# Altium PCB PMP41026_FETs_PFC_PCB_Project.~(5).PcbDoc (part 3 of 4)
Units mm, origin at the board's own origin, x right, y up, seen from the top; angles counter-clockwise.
Board outline 62 x 36 mm, 6 copper layers (Top Layer, Signal Layer 1, Signal Layer 2, Signal Layer 3, Signal Layer 4, Bottom Layer), stack 1.773 mm thick; 61 components, 66 nets, 254 pads, 775 vias.
Unrouted connection lines stored in the file: 2.

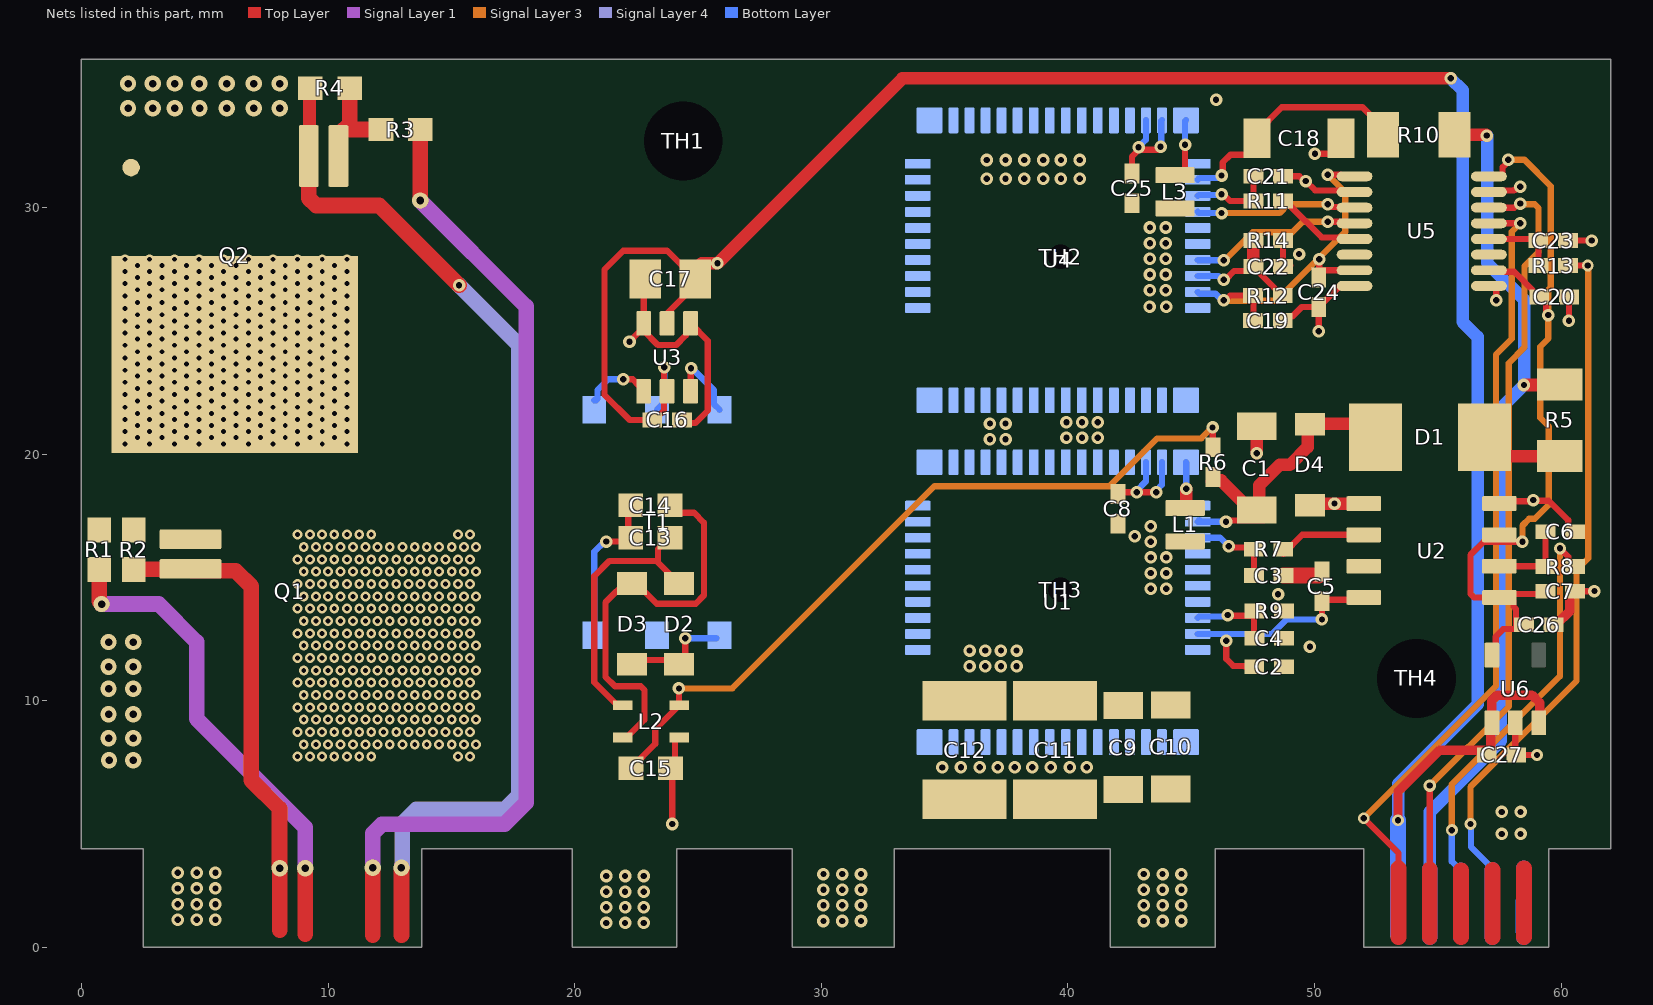
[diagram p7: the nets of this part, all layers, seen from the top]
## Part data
C1 C18: library part CMP-0008692-2, "CAP, CERM, 10 uF, 25 V, +/- 20%, X7R, 1206_190", Cap_Case=1206, Manufacturer=TDK, Supplier Part Number 1=445-6812-1-ND, TempCo=X7R, Tolerance_%=20%, Value1=Unknown, Value2=25V, ValueDisplayed=10uF
C2 C19: library part CMP-0860563-1, "CAP, CERM, 0.22 µF, 16 V,+/- 10%, X7R, 0402", Cap_Case=0402, Manufacturer="Samsung Electro-Mechanics", TempCo=X7R, Tolerance_%=10%, Value2=16V, ValueDisplayed=0.22µF
C3 C4 C6 C21 C22 C23: library part CMP-0006196-2, "CAP, CERM, 100 pF, 50 V, +/- 1%, C0G/NP0, 0402", Cap_Case=0402, Manufacturer=AVX, Supplier Part Number 1=478-3658-1-ND, TempCo=C0G/NP0, Tolerance_%=1%, Value1=Unknown, Value2=50V, ValueDisplayed=100pF
C5 C16 C24: library part CMP-0006297-2, "CAP, CERM, 0.1 uF, 50 V, +/- 10%, X7R, 0402", Alternate Manufacturer="Wurth Elektronik", Alternate PartNumber=885012205037, Cap_Case=0402, Manufacturer=TDK, Supplier Part Number 1=445-5932-1-ND, TempCo=X7R, Tolerance_%=10%, Value1="0.039064 ohm", Value2=50V, ValueDisplayed=0.1uF
C7 C20: library part CMP-0006276-2, "CAP, CERM, 1 uF, 25 V, +/- 10%, X5R, 0402", Alternate Manufacturer=TDK, Alternate PartNumber=C1005X5R1E225K050BC, Cap_Case=0402, Supplier Part Number 1=445-9066-1-ND, TempCo=X5R, Tolerance_%=10%, Value1=Unknown, Value2=25V, ValueDisplayed=1uF
C8 C25: library part CMP-0006716-2, "CAP, CERM, 2.2 uF, 25 V, +/- 10%, X5R, AEC-Q200 Grade 3, 0402", Cap_Case=0402, Manufacturer=MuRata, Supplier Part Number 1=490-12267-1-ND, TempCo=X5R, Tolerance_%=10%, Value1=Unknown, Value2=25V, ValueDisplayed=2.2uF
C9 C10: library part CMP-0084048-1, "CAP, CERM, 0.022 µF, 1000 V,+/- 10%, X7R, AEC-Q200 Grade 1, 1206", Cap_Case=1206, Manufacturer=Kemet, TempCo=X7R, Tolerance_%=10%, Value2=1000V, ValueDisplayed=0.022µF
C11 C12: library part CMP-0009326-2, "CAP, CERM, 0.1 uF, 1000 V, +/- 10%, X7R, 1812", Cap_Case=1812, Manufacturer=Kemet, Supplier Part Number 1=399-6523-1-ND, TempCo=X7R, Tolerance_%=10%, Value1=Unknown, Value2=1000V, ValueDisplayed=0.1uF
C13 C14 C15: library part CMP-0007022-5, "CAP, CERM, 4.7 uF, 35 V, +/- 10%, X5R, 0603", Cap_Case=0603, Manufacturer=TDK, Supplier Part Number 1=445-9064-1-ND, TempCo=X5R, Tolerance_%=10%, Value1="0.003728 ohm", Value2=35V, ValueDisplayed=4.7uF
C17: library part CMP-0008020-2, "CAP, CERM, 4.7 uF, 16 V, +/- 10%, X7R, AEC-Q200 Grade 1, 0805", Cap_Case=0805, Manufacturer=MuRata, Supplier Part Number 1=490-5332-1-ND, TempCo=X7R, Tolerance_%=10%, Value1=Unknown, Value2=16V, ValueDisplayed=4.7uF
C26 C27: library part CMP-0006623-2, "CAP, CERM, 0.1 uF, 6.3 V, +/- 10%, X7R, 0402", Cap_Case=0402, Manufacturer=MuRata, Supplier Part Number 1=GRM155R70J104KA01D-ND, TempCo=X7R, Tolerance_%=10%, Value1=Unknown, Value2=6.3V, ValueDisplayed=0.1uF
D1: library part CMP-0076998-2, "Diode, Schottky, 650 V, 1 A, SMB", Manufacturer="GeneSiC Semiconductor", Value1=1A, Value2=2V
D2 D3: library part CMP-0028524-2, "Diode, Schottky, 20 V, 0.5 A, SOD-123", Manufacturer="ON Semiconductor", Value1=0.5A, Value2=0.385V
D4: library part CMP-0005769-4, "Diode, Zener, 16 V, 500 mW, AEC-Q101, SOD-123", Manufacturer="Diodes Inc.", Power_W=500mW, Value1=0.5W
L1 L3: library part CMP-0089347-1, "4.7µH Unshielded Inductor 1.1A 426mOhm Max 0806 (2016 Metric)", Digikey Part Number=2037-SDEM20161T-4R7MSCT-ND, Manufacturer=Cyntec, Operating Temperature Range="-55°C to +125°C", Test Frequency=1MHz, Tolerance_%=20%
L2: library part CMP-0013161-2, "Coupled inductor, 0.2 A, 0.45 ohm, SMD", Manufacturer=TDK, Supplier Part Number 1=445-8930-1-ND
Q1 Q2: library part CMP-0086487-1, "N-Channel 600V 23A (Tc) 390W (Tc) Surface Mount PG-HSOF-8-2", Manufacturer=Infineon
R1 R3: library part CMP-0022003-4, "RES, 10.0, 1%, 0.1 W, AEC-Q200 Grade 0, 0603", Manufacturer=Vishay-Dale, Power_W=100mW, Supplier Part Number 1=541-10.0HCT-ND, TempCo="100 ppm/C", Tolerance_%=1%, Value2=0.1W, Value_Code=10R0, ValueDisplayed=10.0
R2 R4: library part CMP-0021998-4, "RES, 10.0 k, 1%, 0.1 W, AEC-Q200 Grade 0, 0603", Manufacturer=Vishay-Dale, Power_W=100mW, Supplier Part Number 1=541-10.0KHCT-ND, TempCo="100 ppm/C", Tolerance_%=1%, Value2=0.1W, Value_Code=10k0, ValueDisplayed=10.0k
R5: library part CMP-0018623-3, "RES, 1.8, 5%, 0.25 W, AEC-Q200 Grade 0, 1206", Manufacturer=Vishay-Dale, Power_W=250mW, Supplier Part Number 1=541-1.8ECT-ND, TempCo="200 ppm/C", Tolerance_%=5%, Value2=0.25W, Value_Code=1R80, ValueDisplayed=1.8
R6 R12: library part CMP-0026992-3, "RES, 0, 5%, 0.1 W, AEC-Q200 Grade 0, 0402", Manufacturer=Panasonic, Power_W=100mW, Supplier Part Number 1=P0.0JCT-ND, TempCo="600 ppm/C", Tolerance_%=5%, Value2=0.1W, Value_Code=0000, ValueDisplayed=0
R7 R8 R11 R13: library part CMP-0026738-1, "RES, 49.9, 1%, 0.063 W, 0402", Manufacturer="Yageo America", Power_W=63mW, Supplier Part Number 1=311-49.9LRCT-ND, TempCo="100 ppm/C", Tolerance_%=1%, Value2=0.063W, Value_Code=49R9, ValueDisplayed=49.9
R9 R14: library part CMP-0026162-1, "RES, 20.0 k, 1%, 0.063 W, 0402", Manufacturer=Vishay-Dale, Power_W=63mW, Supplier Part Number 1=541-20.0KLCT-ND, TempCo="100 ppm/C", Tolerance_%=1%, Value2=0.063W, Value_Code=20k0, ValueDisplayed=20.0k
R10: library part CMP-0018748-3, "RES, 0, 5%, 0.25 W, AEC-Q200 Grade 0, 1206", Manufacturer=Panasonic, Power_W=250mW, Supplier Part Number 1=P0.0ECT-ND, TempCo="600 ppm/C", Tolerance_%=5%, Value2=0.25W, Value_Code=0000, ValueDisplayed=0
T1: library part CMP-0030718-1, "Transformer, 475uH, SMT", Manufacturer="Wurth Elektronik", Supplier Part Number 1=732-4458-1-ND, ValueDisplayed=475uH
TH1 TH2 TH3 TH4: library part CMP-0003719-1, "Testpoint", Manufacturer="Texas Instruments", PartNumber=TP_H0.45P0.75
U1 U4: library part CMP-0089968-1, "650-V 30-m? GaN FET with Integrated Driver and Protection", Manufacturer="Texas Instruments", Max Supply Voltage=18V, Min Supply Voltage=7.5V, Nominal Supply Current=540uA, Operating Temperature Range="-40°C to +125°C", Output Voltage=520V
U2: library part CMP-0082403-1, "Automotive, High Speed, Robust EMC Reinforced Single-Channel Digital Isolator, D0008B (SOIC-8)", Alternate Manufacturer="Texas Instruments", Alternate PartNumber=ISO7710FQDRQ1, Operating Temperature Range="-40 to 125 C", Rating=Automotive
U3: library part CMP-0076095-1, "Low-Noise 1 A, 420 kHz Transformer Driver, DBV0006A (SOT-23-6)", Alternate Manufacturer="Texas Instruments", Alternate PartNumber=SN6505BDBVT
U5: library part CMP-0078719-1, "High Speed, Robust EMC Triple-Channel Digital Isolators, DBQ0016A (SSOP-16)", Alternate Manufacturer="Texas Instruments", Alternate PartNumber=ISO7731FDBQ
U6: library part CMP-0065092-2, "Low-Dropout Regulator, DBV0005A (SOT-23-5)", Alternate Manufacturer="Texas Instruments"

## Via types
v1: diameter 0.403, hole 0.2, Top Layer to Bottom Layer, 568 vias
v2: diameter 0.508, hole 0.254, Top Layer to Bottom Layer, 151 vias
v3: diameter 0.66/0.66/0.66/0.66/0.66/0.66 (per signal layer), hole 0.305, Top Layer to Bottom Layer, 32 vias
v4: diameter 0.508, hole 0.254, Top Layer to Bottom Layer, tented top, 11 vias
v5: diameter 0.483, hole 0.254, Top Layer to Bottom Layer, tented both sides, 7 vias
v6: diameter 0.508, hole 0.254, Top Layer to Bottom Layer, tented both sides, 6 vias

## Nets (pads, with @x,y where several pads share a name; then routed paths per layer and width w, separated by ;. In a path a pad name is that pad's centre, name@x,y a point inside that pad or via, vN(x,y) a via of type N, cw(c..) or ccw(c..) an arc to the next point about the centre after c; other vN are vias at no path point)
3V3: C7.1 C20.2 C26.1 U2.1 U2.3 U5.10 U5.16 U6.5 | length 32.5
  Top Layer w0.254: U6.5@57.208,11.934 57.343,12.07 57.343,12.599 57.649,12.904 C26.1@58.164,12.904 ; U5.16@57.357,31.261 57.554,31.261 57.622,31.328 57.622,31.631 57.851,31.86 v2(57.851,31.929) ; U2.1@57.494,14.074 58.004,14.074 58.067,14.011 58.067,13.814 58.164,13.718 C26.1@58.164,12.904 ; U2.3@57.494,16.724 U2.3@57.919,16.724 ; U5.10@57.519,27.387 58.097,27.387 C20.2@59.113,26.371 ; v6(58.429,16.441) 56.852,16.441 56.321,15.91 56.321,14.333 56.47,14.184 U2.1@57.494,14.184 57.639,14.328 59.251,14.328 C7.1@59.36,14.438 ; C26.1@58.491,13.077 58.318,12.904 C26.1@58.164,12.904 ; C20.2@59.17,26.244 59.34,26.244 59.386,26.198 v4@59.386,25.794
  Signal Layer 3 w0.254: v2(57.851,31.929) 58.512,31.929 59.578,30.863 59.578,26.757 59.477,26.656 v4(59.477,25.634) 59.477,24.682 59.146,24.351 59.146,21.471 59.496,21.121 59.496,17.939 58.93,17.373 58.698,17.373 58.429,17.104 v6(58.429,16.441)
5V: C16.1 C17.1 C27.1 T1.5 U3.2 U3.5 U6.1 U6.3 | length 97.5
  Top Layer w0.254: C16.1@22.857,21.384 22.222,21.384 21.206,22.4 21.206,27.48 21.968,28.242 23.746,28.242 C17.1@24.889,27.099 ; C16.1@23.119,21.257 23.619,21.757 U3.2@23.619,22.4 ; U3.2@23.619,22.969 23.619,23.51 v2(23.63,23.521) ; U3.5@23.746,25.702 C17.1@24.889,26.845
  Top Layer w0.381: v5(53.381,5.15) 53.381,6.31 55.068,7.997 56.972,7.997 57.034,7.997 57.144,8.106 57.144,9.057 U6.1@57.188,9.101 57.188,10.003 57.412,10.226 58.813,10.226 59.127,9.912 59.127,9.14 U6.3@59.088,9.101
  Top Layer w0.508: C17.1@25.143,27.734 v4(25.786,27.734) 33.287,35.234 v2(55.519,35.234)
  Bottom Layer w0.254: T1.5@23.335,21.8 23.63,22.095 v2(23.63,23.521)
  Bottom Layer w0.508: v5@53.4,5.233 53.4,6.639 56.608,9.847 56.608,24.75 56,25.358 56,34.753 v2(55.519,35.234)
  Bottom Layer w0.635: 53.381,0.521 v5(53.381,5.15)
5V_H: C2.2 C5.1 U1.51 U2.8 | length 9.9
  Top Layer w0.254: v2(46.422,12.433) 46.422,11.694 46.705,11.411 C2.2@47.444,11.411 ; C2.2@47.197,11.369 47.486,11.369 C2.2@47.444,11.411 ; v4(50.299,13.295) C5.1@50.299,13.93 ; C5.1@50.299,14.092 U2.8@51.604,14.092 ; C2.2@47.444,11.411 47.197,11.411 C2.2@47.444,11.411
  Bottom Layer w0.254: U1.51@45.261,12.708 46.476,12.708 48.286,12.708 48.872,13.295 v4(50.299,13.295)
5V_L: C19.2 C24.2 R12.1 U4.51 U5.1 U5.7 | length 14.5
  Top Layer w0.254: v2(46.318,26.232) 46.387,26.232 46.582,26.427 R12.1@47.507,26.427 47.521,26.427 47.521,25.736 ; C24.2@50.171,27.162 50.191,27.182 C24.2@50.191,27.451 ; v2(50.191,27.895) C24.2@50.191,27.451 ; v2(50.534,31.324) U5.1@51.042,31.324 ; U5.7@51.619,27.451 C24.2@50.191,27.451
  Signal Layer 3 w0.254: v2@46.335,26.214 48.448,26.214 51.241,29.008 51.241,30.617 v2(50.534,31.324)
  Bottom Layer w0.254: U4.51@45.261,26.571 45.334,26.498 45.983,26.498 46.266,26.214 v2@46.335,26.214
12V: R5.1 R10.1 | length 38.6
  Top Layer w0.508: R10.1@55.681,32.946 56.95,32.946 v6(56.981,32.916) ; v2(58.491,22.801) 59.931,22.801 R5.1@59.948,22.817
  Bottom Layer w0.508: 54.666,2.092 54.67,2.097 54.67,5.488 57.551,8.369 57.551,21.861 58.51,22.82 58.51,26.241 57,27.751 57,32.897 v6(56.981,32.916)
  Bottom Layer w0.635: 54.666,0.415 54.673,3.168
+BRDG_N: R1.1 | length 19.6
  Top Layer w0.635: R1.1@0.714,15.319 0.714,14.026 0.814,13.926 v3(0.814,13.919) ; 9.078,0.543 v3(9.078,3.202)
  Signal Layer 1 w0.635: v3(0.814,13.919) 3.134,13.919 4.669,12.383 4.669,9.27 9.078,4.861 v3(9.078,3.202)
+BRDG_P: R3.1 | length 39.9
  Top Layer w0.508: v3(13.732,30.282) v3@13.737,30.287 ; R3.1@13.737,33.154 R3.1@13.742,33.159
  Top Layer w0.635: 11.81,0.501 v3(11.81,3.223) ; v3@13.737,30.287 R3.1@13.737,33.154
  Signal Layer 1 w0.508: v3(13.732,30.282) v3@13.752,30.262
  Signal Layer 1 w0.635: v3(11.81,3.223) 11.81,4.618 12.182,4.99 17.154,4.99 18.028,5.864 18.028,25.985 v3@13.74,30.273
AGND: C6.2 C7.2 C16.2 C17.2 C20.1 C23.2 C26.2 C27.2 U2.4 U3.4 U3.6 U5.9 U5.15 U6.2 | length 33.9
  Top Layer w0.254: v4(22.222,24.559) U3.6@22.603,24.94 ; U3.6@22.796,25.001 23.373,24.424 24.119,24.424 U3.4@24.508,24.813 ; U3.6@22.796,25.299 C17.2@22.796,26.53 ; C16.2@24.254,21.257 24.889,21.257 25.397,21.765 25.397,24.598 U3.4@24.696,25.299 ; U5.9@57.138,26.752 57.366,26.752 57.37,26.749 v2(57.37,26.235) ; U2.4@57.494,17.994 57.587,18.087 58.816,18.087 v2(58.865,18.136) 58.889,18.112 59.497,18.112 60.287,17.322 60.287,17.024 60.46,16.851 C6.2@60.551,16.851 ; U5.15@57.646,30.689 58.076,30.689 58.103,30.716 58.138,30.716 58.265,30.843 v2(58.334,30.843) ; U6.2@58.138,9.101 58.138,8.031 C27.2@58.172,7.997 ; C27.2@58.181,7.799 v5(59.017,7.799) ; v2(60.313,25.404) C20.1@60.313,26.371 ; 60.694,28.657 v4(61.238,28.657) ; C7.2@60.708,14.443 60.71,14.441 61.343,14.441 v2(61.346,14.443)
  Top Layer w0.381: C26.2@59.691,13.077 59.791,13.077 60.351,13.638 60.351,14.328 60.46,14.438 C7.2@60.56,14.438
  Top Layer w0.635: 55.938,0.413 55.938,3.119 ; 57.212,0.412 57.212,3.133 ; 58.491,0.421 58.491,3.204
  Bottom Layer w0.635: 58.47,0.66 58.48,3.202 58.48,0.41
  other v2: 57.591,4.599 58.353,4.599 57.591,5.488 58.353,5.488 46.007,34.365
Bot_FET_FAULT: U5.14 | length 33.6
  Top Layer w0.254: 54.67,3.165 v6(54.67,6.56) ; U5.14@57.069,29.991 58.099,29.991 58.265,30.158 v6(58.334,30.158)
  Top Layer w0.635: 54.67,0.41 54.67,3.165 54.676,3.171
  Signal Layer 3 w0.254: v6(54.67,6.56) 57.871,9.76 57.871,23.686 58.513,24.329 58.513,27.62 59.075,28.182 59.075,29.982 58.926,30.131 58.361,30.131 v6(58.334,30.158)
ISO_12V_H: C15.1 L2.2 R6.1 | length 30.9
  Top Layer w0.254: C15.1@22.281,7.258 23.27,8.247 23.27,8.839 L2.2@24.243,9.813 24.224,9.833 v4(24.224,10.497) ; v2(45.861,21.08) 45.873,21.069 45.873,20.285 R6.1@45.884,20.274
  Signal Layer 3 w0.254: v4(24.224,10.497) 26.385,10.497 34.584,18.696 41.676,18.696 42.097,19.117 43.615,20.635 45.408,20.635 45.854,21.08 v2(45.861,21.08)
NC1: TH1.1
NC2: TH3.1
NC3: TH2.1
NC4: TH4.1
NCT1: T1.2
NCU51: U1.1
NCU61: U4.1
NCU516: U1.16
NCU527: U1.27
NCU543: U1.43
NCU547: U1.47
NCU552: U1.52
NCU616: U4.16
NCU627: U4.27
NCU643: U4.43
NCU647: U4.47
NCU652: U4.52
NetC1_1: C1.1 D1.1 D4.1 R6.2 U1.44 | length 12.3
  Top Layer w0.254: R6.2@45.711,18.901 R6.2@45.884,19.074 ; v4(46.408,17.258) 46.455,17.305 47.943,17.305 C1.1@48.165,17.527
  Top Layer w0.508: R6.2@45.884,19.074 45.884,18.974 45.93,18.928 46.208,18.928 47.408,17.728 C1.1@47.658,17.728 47.763,17.833 47.763,18.743 48.586,19.566 48.999,19.566 49.714,20.281 49.714,21.106 D4.1@49.812,21.203 ; D4.1@50.194,21.225 D1.1@52.146,21.225
  Bottom Layer w0.254: U1.44@45.334,17.331 U1.44@45.261,17.258 v4(46.408,17.258)
NetC3_2: C3.2 R7.1 U1.45 | length 3.3
  Top Layer w0.254: v2(46.516,16.259) 46.564,16.21 47.451,16.21 R7.1@47.522,16.139 ; C3.2@47.54,15.073 R7.1@47.54,15.962
  Bottom Layer w0.254: U1.45@45.261,16.608 46.167,16.608 v2(46.516,16.259)
NetC4_2: C4.2 R9.2 U1.50 | length 3.2
  Top Layer w0.254: v2(46.476,13.47) 46.5,13.446 47.516,13.446 47.54,13.422 C4.2@47.54,12.538
  Bottom Layer w0.254: U1.50@45.261,13.358 45.317,13.414 46.352,13.414 46.408,13.47 v2(46.476,13.47)
NetC6_1: C6.1 R8.2 U2.2 | length 3.3
  Top Layer w0.254: U2.2@57.494,15.454 59.347,15.454 R8.2@59.36,15.44 C6.1@59.36,16.851
NetC8_1: C8.1 U1.40 U1.41 | length 4.3
  Top Layer w0.254: C8.1@42.026,18.376 42.102,18.452 v2(42.794,18.452) v2(43.579,18.452)
  Bottom Layer w0.254: v2(42.794,18.452) 42.794,18.521 43.161,18.887 U1.40@43.161,19.668 ; v2(43.579,18.452) 43.579,18.521 43.811,18.752 U1.41@43.811,19.668
NetC13_1: C13.1 D2.1 L2.3 | length 10.9
  Top Layer w0.254: L2.3@21.943,9.813 21.732,9.813 20.795,10.751 20.795,15.052 21.408,15.665 23.247,15.665 ; C13.1@23.754,16.608 23.754,16.52 23.373,16.139 23.373,15.609 23.881,15.101 24.068,14.913 D2.1@24.229,14.752
NetC13_2: C13.2 C14.1 T1.3 | length 6.4
  Top Layer w0.254: v2(21.276,16.453) 22.111,16.453 C13.2@22.267,16.608 ; C13.2@22.154,16.608 22.171,16.626 C14.1@22.171,17.863
  Bottom Layer w0.254: T1.3@20.795,12.656 20.795,16.041 21.207,16.453 v2(21.276,16.453)
NetC14_2: C14.2 D3.2 L2.4 | length 15.9
  Top Layer w0.254: L2.4@22.192,8.592 22.827,9.227 22.827,10.437 22.678,10.586 21.635,10.586 21.245,10.976 21.245,13.981 D3.2@22.192,14.928 ; D3.2@22.7,14.561 23.327,13.933 24.909,13.933 25.24,14.264 25.24,17.22 24.839,17.621 24.013,17.621 C14.2@23.771,17.863
NetC18_1: C18.1 R10.2 U4.44 | length 9.9
  Top Layer w0.254: v2(46.23,31.295) 46.278,31.343 46.278,31.824 46.59,32.135 47.248,32.135 47.671,32.558 47.671,33.058 48.671,34.058 51.944,34.058 52.781,33.221 R10.2@52.781,32.946
  Bottom Layer w0.254: U4.44@45.261,31.121 45.334,31.194 46.06,31.194 46.161,31.295 v2(46.23,31.295)
NetC21_2: C21.2 R11.2 U4.45 | length 3.5
  Top Layer w0.254: v2(46.23,30.533) 46.298,30.533 46.574,30.256 47.47,30.256 47.522,30.308 47.522,31.178 47.521,31.179 C21.2@47.376,31.324
  Bottom Layer w0.254: U4.45@45.261,30.471 45.291,30.502 46.199,30.502 v2(46.23,30.533)
NetC22_2: C22.2 R12.2 R14.2 U4.50 | length 5.1
  Top Layer w0.254: v2(46.318,27.072) 46.387,27.072 46.741,27.426 47.348,27.426 C22.2@47.521,27.599 48.693,26.427 R12.2@48.707,26.427 ; 47.477,27.94 C22.2@47.521,27.895
  Top Layer w0.508: C22.2@47.521,27.895 R14.2@47.521,28.657
  Bottom Layer w0.254: U4.50@45.261,27.221 46.101,27.221 46.266,27.055 v2@46.335,27.055
NetC23_1: C23.1 R13.2 U5.12 | length 2.8
  Top Layer w0.254: U5.12@57.069,28.721 C23.1@59.008,28.721 ; C23.1@59.071,28.657 59.078,28.651 R13.2@59.078,27.768
NetC25_1: C25.1 U4.40 U4.41 | length 4.3
  Top Layer w0.254: C25.1@42.594,31.372 42.594,32.062 42.864,32.332 42.871,32.34 43.748,32.34 v2@43.755,32.347
  Bottom Layer w0.254: v2(42.864,32.441) 43.161,32.738 U4.40@43.161,33.531 ; v2(43.755,32.455) 43.783,32.483 43.783,33.503 U4.41@43.811,33.531
NetD1_2: D1.2 R5.2 | length 3.4
  Top Layer w0.508: D1.2@56.886,20.686 57.654,19.917 R5.2@59.948,19.917
NetD2_2: D2.2 D3.1 T1.1 | length 3.8
  Top Layer w0.254: D3.1@22.192,11.653 D2.2@23.956,11.653 ; D2.2@24.478,11.767 v2(24.478,12.529)
  Bottom Layer w0.254: v2(24.478,12.529) T1.1@25.748,12.529
NetL1_2: L1.2 U1.42 | length 1.9
  Top Layer w0.254: v2(44.793,18.593) v2@44.842,18.642
  Top Layer w0.508: L1.2@44.748,17.808 44.793,17.853 v2(44.793,18.593)
  Bottom Layer w0.254: U1.42@44.786,19.668 44.793,19.661 v2@44.793,18.692
NetL3_2: L3.2 U4.42 | length 2.5
  Top Layer w0.254: L3.2@44.34,31.309 44.55,31.309 44.748,31.507 v2(44.748,32.539)
  Bottom Layer w0.254: v2(44.748,32.539) 44.748,33.493 U4.42@44.786,33.531
NetQ1_1: Q1.1 R1.2 R2.2
NetQ2_1: Q2.1 R3.2 R4.2 | length 3.2
  Top Layer w0.635: R4.2@10.872,34.829 10.872,33.385 10.646,33.159 10.872,33.159 R3.2@12.109,33.159
NetR7_2: R7.2 U2.6 | length 3.1
  Top Layer w0.254: R7.2@48.74,15.962 49.502,16.724 U2.6@51.569,16.724
NetR11_1: R11.1 U5.5 | length 3
  Top Layer w0.254: R11.1@48.722,30.308 R11.1@48.883,30.308 ; R11.1@48.883,30.187 50.285,28.784 U5.5@51.169,28.784
NetT1_4: T1.4 U3.1 | length 2.5
  Top Layer w0.254: v4(21.968,23.035) 22.349,23.035 U3.1@22.603,22.781
  Bottom Layer w0.254: T1.4@20.795,22.181 20.872,22.181 20.922,22.232 20.922,22.591 21.366,23.035 v4(21.968,23.035)
NetT1_6: T1.6 U3.3 | length 2.8
  Top Layer w0.254: v2(24.718,23.482) 24.707,23.471 24.707,22.922 24.721,22.908 U3.3@24.762,22.908
  Bottom Layer w0.254: v2(24.718,23.482) 24.755,23.482 25.646,22.591 25.646,22.028 T1.6@25.875,21.8
NetU4_46: U4.46 U5.3 | length 6.7
  Top Layer w0.254: v2(50.534,30.131) 50.603,30.131 50.714,30.019 51.591,30.019 U5.3@51.619,29.991
  Signal Layer 3 w0.254: v2(46.23,29.771) 48.579,29.771 48.939,30.131 v2(50.534,30.131)
  Bottom Layer w0.254: U4.46@45.261,29.821 45.311,29.771 v2(46.23,29.771) v2@46.278,29.722
NetU4_49: U4.49 U5.4 | length 6.7
  Top Layer w0.254: v2(50.534,29.419) U5.4@51.296,29.419
  Signal Layer 3 w0.254: v2@46.335,27.836 47.498,28.999 49.098,28.999 49.518,29.419 v2(50.534,29.419)
  Bottom Layer w0.254: U4.49@45.261,27.871 45.278,27.854 v2(46.318,27.854) v2@46.335,27.836
Neutral: Q1.2 Q2.9 R2.1 | length 24.9
  Top Layer w0.254: Q2.9@2.724,24.043 Q2.9@4.264,24.043 ; Q2.9@3.264,24.043 Q2.9@4.264,24.043 ; Q2.9@5.264,24.043 6.224,24.043 Q2.9@4.264,24.043
  Top Layer w0.635: R2.1@2.128,15.319 2.142,15.332 4.408,15.332 Q1.2@4.421,15.345 4.504,15.263 6.258,15.263 6.884,14.637 6.884,6.776 8.033,5.627 8.033,3.207 v3(8.038,3.202) 8.038,0.687
  other v1: 1.764,20.413 2.764,20.413 3.764,20.413 4.764,20.413 5.764,20.413 6.764,20.413 7.764,20.413 8.764,20.413 9.764,20.413 10.764,20.413 2.264,20.663 3.264,20.663 4.264,20.663 5.264,20.663 6.264,20.663 7.264,20.663 8.264,20.663 9.264,20.663 10.264,20.663 1.764,20.913 2.764,20.913 3.764,20.913 4.764,20.913 5.764,20.913 6.764,20.913 7.764,20.913 8.764,20.913 9.764,20.913 10.764,20.913 2.264,21.163 3.264,21.163 4.264,21.163 5.264,21.163 6.264,21.163 7.264,21.163 8.264,21.163 9.264,21.163 10.264,21.163 1.764,21.399 2.764,21.399 3.764,21.399 4.764,21.399 5.764,21.399 6.764,21.399 7.764,21.399 8.764,21.399 9.764,21.399 10.764,21.399 2.264,21.649 3.264,21.649 4.264,21.649 5.264,21.649 6.264,21.649 7.264,21.649 8.264,21.649 9.264,21.649 10.264,21.649 1.764,21.899 2.764,21.899 3.764,21.899 4.764,21.899 5.764,21.899 6.764,21.899 7.764,21.899 8.764,21.899 9.764,21.899 10.764,21.899 2.264,22.149 3.264,22.149 4.264,22.149 5.264,22.149 6.264,22.149 7.264,22.149 8.264,22.149 9.264,22.149 10.264,22.149 1.764,22.413 2.764,22.413 3.764,22.413 4.764,22.413 5.764,22.413 6.764,22.413 7.764,22.413 8.764,22.413 9.764,22.413 10.764,22.413 2.264,22.663 3.264,22.663 4.264,22.663 5.264,22.663 6.264,22.663 7.264,22.663 8.264,22.663 9.264,22.663 10.264,22.663 1.764,22.913 2.764,22.913 3.764,22.913 4.764,22.913 5.764,22.913 6.764,22.913 7.764,22.913 8.764,22.913 9.764,22.913 10.764,22.913 2.264,23.163 3.264,23.163 4.264,23.163 5.264,23.163 6.264,23.163 7.264,23.163 8.264,23.163 9.264,23.163 10.264,23.163 1.764,23.399 2.764,23.399 3.764,23.399 4.764,23.399 5.764,23.399 6.764,23.399 7.764,23.399 8.764,23.399 9.764,23.399 10.764,23.399 2.264,23.649 3.264,23.649 4.264,23.649 5.264,23.649 6.264,23.649 7.264,23.649 8.264,23.649 9.264,23.649 10.264,23.649 1.764,23.899 2.764,23.899 3.764,23.899 4.764,23.899 5.764,23.899 6.764,23.899 7.764,23.899 8.764,23.899 9.764,23.899 10.764,23.899 2.264,24.149 3.264,24.149 4.264,24.149 5.264,24.149 6.264,24.149 7.264,24.149 8.264,24.149 9.264,24.149 10.264,24.149 1.764,24.413 2.764,24.413 3.764,24.413 4.764,24.413 5.764,24.413 6.764,24.413 7.764,24.413 8.764,24.413 9.764,24.413 10.764,24.413 2.264,24.663 3.264,24.663 4.264,24.663 5.264,24.663 6.264,24.663 7.264,24.663 8.264,24.663 9.264,24.663 10.264,24.663 1.764,24.913 2.764,24.913 3.764,24.913 4.764,24.913 5.764,24.913 6.764,24.913 7.764,24.913 8.764,24.913 9.764,24.913 10.764,24.913 2.264,25.163 3.264,25.163 4.264,25.163 5.264,25.163 6.264,25.163 7.264,25.163 8.264,25.163 9.264,25.163 10.264,25.163 1.764,25.399 2.764,25.399 3.764,25.399 4.764,25.399 5.764,25.399 6.764,25.399 7.764,25.399 8.764,25.399 9.764,25.399 10.764,25.399 2.264,25.649 3.264,25.649 4.264,25.649 5.264,25.649 6.264,25.649 7.264,25.649 8.264,25.649 9.264,25.649 10.264,25.649 1.764,25.899 2.764,25.899 3.764,25.899 4.764,25.899 5.764,25.899 6.764,25.899 7.764,25.899 8.764,25.899 9.764,25.899 10.764,25.899 2.264,26.149 3.264,26.149 4.264,26.149 5.264,26.149 6.264,26.149 7.264,26.149 8.264,26.149 9.264,26.149 10.264,26.149 1.764,26.413 2.764,26.413 3.764,26.413 4.764,26.413 5.764,26.413 6.764,26.413 7.764,26.413 8.764,26.413 9.764,26.413 10.764,26.413 2.264,26.663 3.264,26.663 4.264,26.663 5.264,26.663 6.264,26.663 7.264,26.663 8.264,26.663 9.264,26.663 10.264,26.663 1.764,26.913 2.764,26.913 3.764,26.913 4.764,26.913 5.764,26.913 6.764,26.913 7.764,26.913 8.764,26.913 9.764,26.913 10.764,26.913 2.264,27.163 3.264,27.163 4.264,27.163 5.264,27.163 6.264,27.163 7.264,27.163 8.264,27.163 9.264,27.163 10.264,27.163 1.764,27.399 2.764,27.399 3.764,27.399 4.764,27.399 5.764,27.399 6.764,27.399 7.764,27.399 8.764,27.399 9.764,27.399 10.764,27.399 2.264,27.649 3.264,27.649 4.264,27.649 5.264,27.649 6.264,27.649 7.264,27.649 8.264,27.649 9.264,27.649 10.264,27.649 1.764,27.899 2.764,27.899 3.764,27.899 4.764,27.899 5.764,27.899 6.764,27.899 7.764,27.899 8.764,27.899 9.764,27.899 10.764,27.899
  other v2: 3.907,1.116 4.669,1.116 5.431,1.116 3.907,1.751 4.669,1.751 5.431,1.751 3.907,2.386 4.669,2.386 5.431,2.386 3.907,3.021 4.669,3.021 5.431,3.021
  other v3: 1.12,7.584 2.1,7.584 1.1,8.473 2.1,8.473 1.1,9.455 2.1,9.455 1.1,10.479 2.1,10.479 1.1,11.379 2.1,11.379 1.1,12.378 2.1,12.378
PFC_Temp3: U5.13 | length 33.4
  Top Layer w0.254: v5(51.994,5.233) 53.4,3.827 53.4,3.202 ; U5.13@57.069,29.356 v6(58.334,29.356)
  Top Layer w0.635: 53.4,0.41 53.4,3.202
  Signal Layer 3 w0.254: v5(51.994,5.233) 57.36,10.599 57.36,24.042 57.994,24.676 57.994,29.016 v6(58.334,29.356)
PGND: C9.2 C10.2 C11.2 C12.2 C18.2 C19.1 C21.1 C22.1 C24.1 C25.2 L3.1 Q2.2 Q2.3-4-5-6-7-8 R4.1 R14.1 U4.17 U4.18 U4.19 U4.20 U4.21 U4.22 U4.23 U4.24 U4.25 U4.26 U4.28 U4.29 U4.30 U4.31 U4.32 U4.33 U4.34 U4.35 U4.36 U4.37 U4.38 U4.39 U5.2 U5.8 | length 52
  Top Layer w0.254: C19.1@48.707,25.538 48.753,25.584 49.104,25.584 49.482,25.962 C24.1@50.171,25.962 ; C22.1@48.721,27.768 48.721,28.495 R14.1@48.756,28.53 ; C21.1@48.722,31.261 49.386,31.261 49.576,31.07 v4(49.645,31.07) 50.026,30.689 U5.2@51.042,30.689 ; C22.1@48.883,27.768 C22.1@49.01,27.641 ; v4(50.014,32.173) C18.2@50.641,32.173 ; v2(50.171,24.974) C24.1@50.171,25.962 ; U5.8@51.619,26.816 51.025,26.816 C24.1@50.171,25.962
  Top Layer w0.508: Q2.2@9.22,32.083 9.246,32.109 9.246,34.803 R4.1@9.272,34.829 ; v3(12.974,3.223) v3@13.003,3.252
  Top Layer w0.635: Q2.2@9.22,32.083 9.22,30.373 9.517,30.076 12.078,30.076 v6(15.309,26.845) ; 12.974,0.501 v3(12.974,3.223)
  Signal Layer 1 w0.635: v3(12.974,3.223) v3@12.979,3.228
  Signal Layer 4 w0.635: v3@13.003,3.252 13.003,5.012 13.577,5.586 17.151,5.586 17.741,6.175 17.741,24.413 v6(15.309,26.845)
  other v2: 30.084,1.067 30.846,1.067 31.608,1.067 30.084,1.702 30.846,1.702 31.608,1.702 30.084,2.337 30.846,2.337 31.608,2.337 30.084,2.972 30.846,2.972 31.608,2.972 36.01,11.399 36.645,11.399 37.28,11.399 37.915,11.399 36.01,12.034 36.645,12.034 37.28,12.034 37.915,12.034 43.308,25.969 43.99,25.969 43.326,26.646 43.961,26.646 43.326,27.281 43.961,27.281 43.326,27.916 43.961,27.916 49.371,28.107 43.326,28.551 43.961,28.551 43.326,29.186 43.961,29.186 36.709,31.162 37.471,31.162 38.233,31.162 38.995,31.162 39.716,31.162 40.478,31.162 36.709,31.924 37.471,31.924 38.233,31.924 38.995,31.924 39.716,31.924 40.478,31.924
  other v3: 1.888,34.024 2.888,34.024 3.788,34.024 4.788,34.024 5.888,34.024 6.988,34.024 8.038,34.024 1.888,35.024 2.888,35.024 3.788,35.024 4.78,35.024 5.888,35.024 6.988,35.024 8.038,35.024
SW: C1.2 C2.1 C3.1 C4.1 C5.2 C8.2 C15.2 D4.2 L1.1 L2.1 R9.1 U1.17 U1.18 U1.19 U1.20 U1.21 U1.22 U1.23 U1.24 U1.25 U1.26 U1.28 U1.29 U1.30 U1.31 U1.32 U1.33 U1.34 U1.35 U1.36 U1.37 U1.38 U1.39 U2.5 U4.2 U4.3 U4.4 U4.5 U4.6 U4.7 U4.8 U4.9 U4.10 U4.11 U4.12 U4.13 U4.14 U4.15 | length 8.6
  Top Layer w0.254: v2(23.956,5) 23.956,7.107 23.843,7.22 C15.2@23.881,7.258 24.068,7.446 24.068,8.44 24.141,8.513 L2.1@24.243,8.513 ; v2@43.321,16.492 v2@43.362,16.45 ; L1.1@44.74,16.45 L1.1@44.748,16.458
  Top Layer w0.508: v2(47.658,20.029) C1.2@47.658,21.128 ; D4.2@49.812,17.928 49.877,17.994 v2(50.807,17.994) U2.5@51.994,17.994
  Top Layer w0.635: C3.1@48.74,15.073 C5.2@50.172,15.073
  other v2: 21.279,0.987 22.041,0.987 22.803,0.987 21.279,1.622 22.041,1.622 22.803,1.622 21.279,2.257 22.041,2.257 22.803,2.257 21.279,2.892 22.041,2.892 22.803,2.892 48.521,14.311 43.355,14.538 43.99,14.538 43.355,15.173 43.99,15.173 43.355,15.808 43.99,15.808 43.355,16.443 42.71,16.666 43.355,17.078 36.836,20.601 37.471,20.601 39.938,20.657 40.573,20.657 41.208,20.657 36.836,21.236 37.471,21.236 39.938,21.292 40.573,21.292 41.208,21.292
  other v4: 49.812,12.192
TTP_HSDRV1: R8.1 | length 19.1
  Top Layer w0.254: v5(59.948,16.176) 60.287,15.837 60.287,15.613 60.447,15.454 R8.1@60.551,15.454
  Signal Layer 3 w0.254: v5(55.565,4.75) 55.565,6.603 59.948,10.986 v5(59.948,16.176)
  Bottom Layer w0.254: v5(55.565,4.75) 55.565,3.482 55.94,3.107 55.94,2.821
  Bottom Layer w0.635: 55.928,0.423 55.928,3.118
TTP_LSDRV1: R13.1 | length 33
  Top Layer w0.254: R13.1@60.186,27.641 R13.1@60.278,27.641 v5(61.075,27.641)
  Signal Layer 3 w0.254: v5(56.321,5) 56.321,6.504 60.623,10.806 60.623,15.303 61.094,15.774 61.094,27.622 v5(61.075,27.641)
  Bottom Layer w0.254: v5(56.321,5) 56.347,4.975 56.347,4.066 57.21,3.202 57.21,3.075
  Bottom Layer w0.635: 57.202,0.649 57.202,3.132 ; 57.21,0.41 57.21,3.075
U2NC7: U2.7
U3NC6: U5.6
U3NC11: U5.11
U5FAULT: U1.46
U5OC: U1.48
U5TEMP: U1.49
U6OC: U4.48
Vbulk1: C9.1 C10.1 C11.1 C12.1 U1.2 U1.3 U1.4 U1.5 U1.6 U1.7 U1.8 U1.9 U1.10 U1.11 U1.12 U1.13 U1.14 U1.15
  other v1: 8.764,7.732 9.264,7.732 9.75,7.732 10.25,7.732 10.764,7.732 11.264,7.732 11.75,7.732 15.264,7.732 15.75,7.732 9.014,8.232 9.514,8.232 10,8.232 10.5,8.232 11.014,8.232 11.514,8.232 12,8.232 12.5,8.232 13.014,8.232 13.514,8.232 14,8.232 14.5,8.232 15.014,8.232 15.514,8.232 16,8.232 8.764,8.732 9.264,8.732 9.75,8.732 10.25,8.732 10.764,8.732 11.264,8.732 11.75,8.732 12.25,8.732 12.764,8.732 13.264,8.732 13.75,8.732 14.25,8.732 14.764,8.732 15.264,8.732 15.75,8.732 9.014,9.232 9.514,9.232 10,9.232 10.5,9.232 11.014,9.232 11.514,9.232 12,9.232 12.5,9.232 13.014,9.232 13.514,9.232 14,9.232 14.5,9.232 15.014,9.232 15.514,9.232 16,9.232 8.764,9.732 9.264,9.732 9.75,9.732 10.25,9.732 10.764,9.732 11.264,9.732 11.75,9.732 12.25,9.732 12.764,9.732 13.264,9.732 13.75,9.732 14.25,9.732 14.764,9.732 15.264,9.732 15.75,9.732 9.014,10.232 9.514,10.232 10,10.232 10.5,10.232 11.014,10.232 11.514,10.232 12,10.232 12.5,10.232 13.014,10.232 13.514,10.232 14,10.232 14.5,10.232 15.014,10.232 15.514,10.232 16,10.232 8.764,10.732 9.264,10.732 9.75,10.732 10.25,10.732 10.764,10.732 11.264,10.732 11.75,10.732 12.25,10.732 12.764,10.732 13.264,10.732 13.75,10.732 14.25,10.732 14.764,10.732 15.264,10.732 15.75,10.732 9.014,11.232 9.514,11.232 10,11.232 10.5,11.232 11.014,11.232 11.514,11.232 12,11.232 12.5,11.232 13.014,11.232 13.514,11.232 14,11.232 14.5,11.232 15.014,11.232 15.514,11.232 16,11.232 8.764,11.732 9.264,11.732 9.75,11.732 10.25,11.732 10.764,11.732 11.264,11.732 11.75,11.732 12.25,11.732 12.764,11.732 13.264,11.732 13.75,11.732 14.25,11.732 14.764,11.732 15.264,11.732 15.75,11.732 9.014,12.232 9.514,12.232 10,12.232 10.5,12.232 11.014,12.232 11.514,12.232 12,12.232 12.5,12.232 13.014,12.232 13.514,12.232 14,12.232 14.5,12.232 15.014,12.232 15.514,12.232 16,12.232 8.764,12.732 9.264,12.732 9.75,12.732 10.25,12.732 10.764,12.732 11.264,12.732 11.75,12.732 12.25,12.732 12.764,12.732 13.264,12.732 13.75,12.732 14.25,12.732 14.764,12.732 15.264,12.732 15.75,12.732 9.014,13.232 9.514,13.232 10,13.232 10.5,13.232 11.014,13.232 11.514,13.232 12,13.232 12.5,13.232 13.014,13.232 13.514,13.232 14,13.232 14.5,13.232 15.014,13.232 15.514,13.232 16,13.232 8.764,13.732 9.264,13.732 9.75,13.732 10.25,13.732 10.764,13.732 11.264,13.732 11.75,13.732 12.25,13.732 12.764,13.732 13.264,13.732 13.75,13.732 14.25,13.732 14.764,13.732 15.264,13.732 15.75,13.732 9.014,14.232 9.514,14.232 10,14.232 10.5,14.232 11.014,14.232 11.514,14.232 12,14.232 12.5,14.232 13.014,14.232 13.514,14.232 14,14.232 14.5,14.232 15.014,14.232 15.514,14.232 16,14.232 8.764,14.732 9.264,14.732 9.75,14.732 10.25,14.732 10.764,14.732 11.264,14.732 11.75,14.732 12.25,14.732 12.764,14.732 13.264,14.732 13.75,14.732 14.25,14.732 14.764,14.732 15.264,14.732 15.75,14.732 9.014,15.232 9.514,15.232 10,15.232 10.5,15.232 11.014,15.232 11.514,15.232 12,15.232 12.5,15.232 13.014,15.232 13.514,15.232 14,15.232 14.5,15.232 15.014,15.232 15.514,15.232 16,15.232 8.764,15.732 9.264,15.732 9.75,15.732 10.25,15.732 10.764,15.732 11.264,15.732 11.75,15.732 12.25,15.732 12.764,15.732 13.264,15.732 13.75,15.732 14.25,15.732 14.764,15.732 15.264,15.732 15.75,15.732 9.014,16.232 9.514,16.232 10,16.232 10.5,16.232 11.014,16.232 11.514,16.232 12,16.232 12.5,16.232 13.014,16.232 13.514,16.232 14,16.232 14.5,16.232 15.014,16.232 15.514,16.232 16,16.232 8.764,16.732 9.264,16.732 9.75,16.732 10.25,16.732 10.764,16.732 11.264,16.732 11.75,16.732 15.264,16.732 15.75,16.732
  other v2: 43.076,1.067 43.838,1.067 44.6,1.067 43.076,1.702 43.838,1.702 44.6,1.702 43.076,2.337 43.838,2.337 44.6,2.337 43.076,2.972 43.838,2.972 44.6,2.972 34.9,7.295 35.662,7.296 36.424,7.296 37.153,7.296 37.846,7.296 38.557,7.296 39.303,7.296 40.081,7.296 40.767,7.296
pads on no net: Q1.9 U6.4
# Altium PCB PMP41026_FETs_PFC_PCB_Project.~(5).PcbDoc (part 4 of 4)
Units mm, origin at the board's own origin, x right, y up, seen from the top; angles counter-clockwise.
Board outline 62 x 36 mm, 6 copper layers (Top Layer, Signal Layer 1, Signal Layer 2, Signal Layer 3, Signal Layer 4, Bottom Layer), stack 1.773 mm thick; 61 components, 66 nets, 254 pads, 775 vias.
Unrouted connection lines stored in the file: 2.

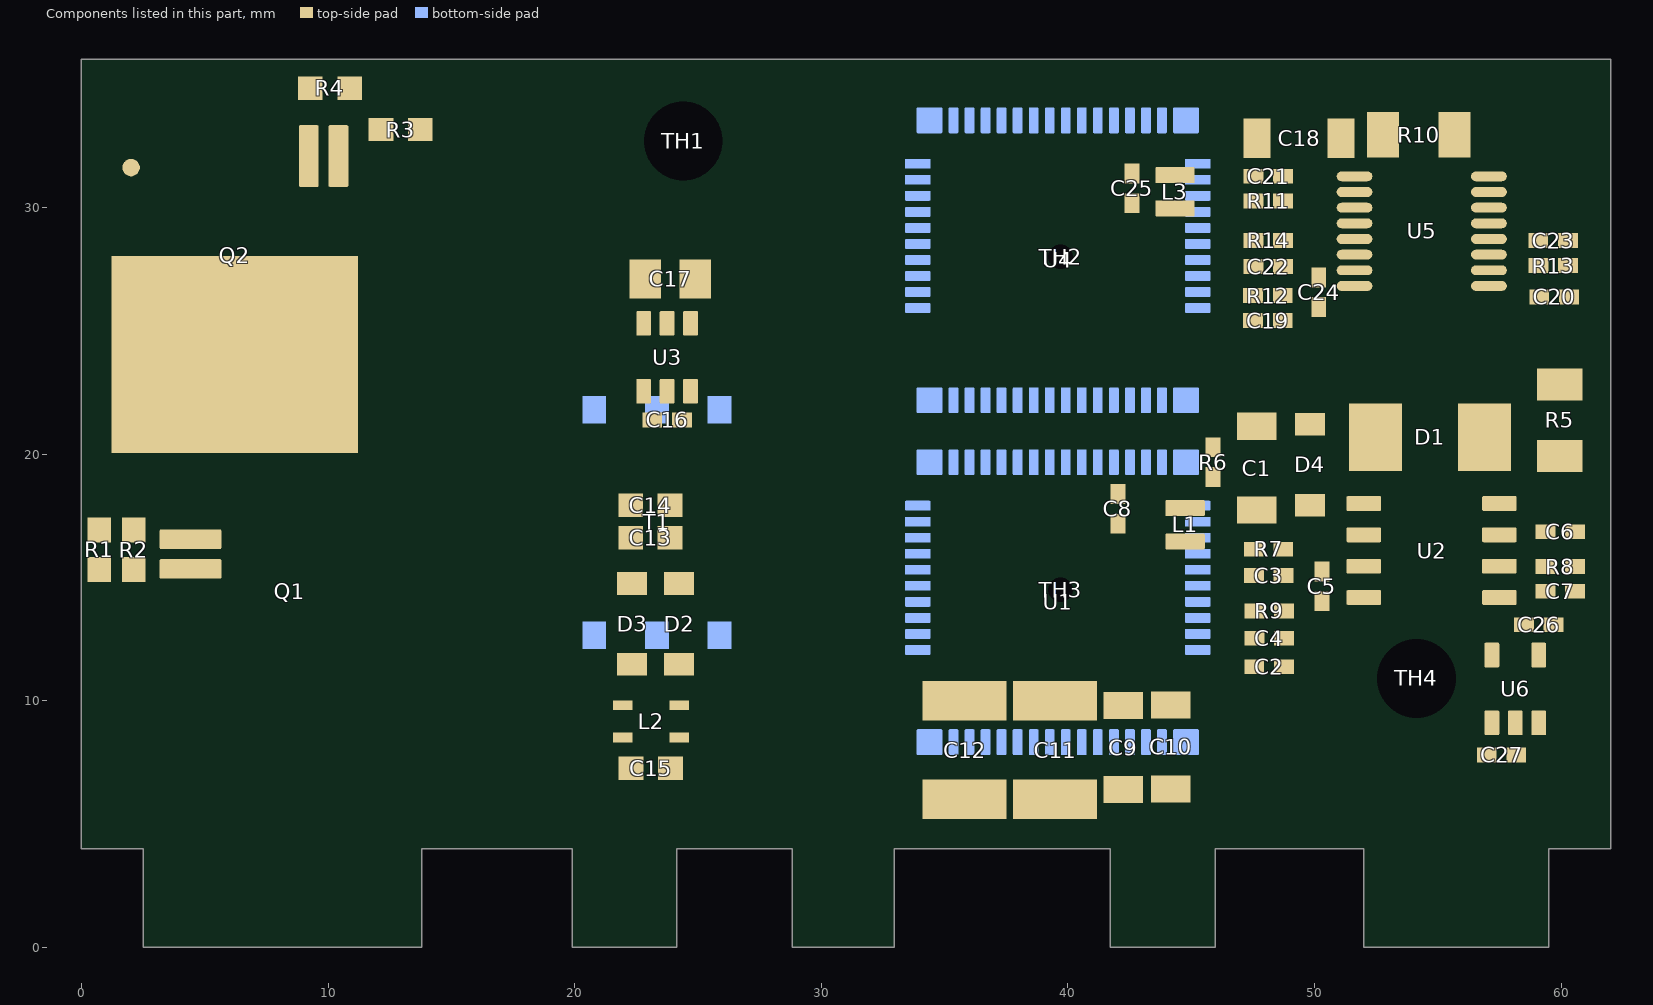
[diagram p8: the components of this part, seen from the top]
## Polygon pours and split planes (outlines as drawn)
Neutral on Bottom Layer "BOTTOM_LAYER_NEUTRAL_P370" (solid, remove dead copper, pour order 370): 4.152,7.584 7,4.736 7,4.111 2.517,4.111 -0.016,6.644 -0.016,7.959 -0.016,19.976 -0.016,27.393 1.128,28.538 10.843,28.538 11.81,27.571 11.81,20.094 11.389,19.674 7.305,19.674 4.152,16.521
Neutral on Bottom Layer "BOTTOM_LAYER_NEUTRAL_P365" (solid, pour order 365): 2.6,4.111 2.6,0 7,0 7,4.111
PGND on Bottom Layer "BOTTOM_LAYER_PGND_P355" (solid, pour order 355): 14.216,31.5 0.956,31.5 0.362,32.094 0.362,35.13 1.231,36 41.07,36 41.82,35.25 42.705,34.365 42.705,33.902 41.433,32.629 39.303,32.629 39.303,29.335 35.041,25.072 20.644,25.072
Vbulk1 on Bottom Layer "BOTTOM_LAYER_VBULK1_P352" (solid, remove dead copper, pour order 352): 19.344,10.101 32.261,10.101 33.785,8.577 40.7,8.577 40.7,5.91 10.333,5.91 8.488,7.755 8.488,17.419 16.48,17.419 16.788,16.96 16.788,12.658
AGND on Bottom Layer "Bottom Layer-AGND" (solid, pour order 320): 58.099,3.202 57.21,4.091 57.21,5.996 57.464,6.25 58.734,6.25 58.988,5.996 58.988,3.456 58.734,3.202
SW on Bottom Layer "Bottom Layer-SW 1" (solid, pour order 319): 44.187,18.063 44.476,17.775 44.476,12.192 43.997,11.713 43.218,11.713 42.71,12.221 42.71,16.666 41.313,18.063 37.877,18.063 35.471,15.658 35.471,12.284 34.9,11.713 33.444,11.713 32.55,12.607 32.55,20.857 42.964,20.857 43.409,20.412 43.409,18.444 43.79,18.063
SW on Bottom Layer "Bottom Layer-SW" (solid, pour order 318): 47.304,22.117 46.217,23.204 32.996,23.204 32.55,22.759 32.55,19.674 47.05,19.674 47.304,19.928
PGND on Bottom Layer "Bottom Layer-PGND 1" (solid, pour order 316): 28.814,3.861 28.814,-0.01 32.878,-0.01 32.878,3.861
no net on Bottom Layer "Bottom Layer-Vbulk+" (solid, pour order 315): 41.716,4.091 41.716,0.093 45.907,0.093 45.907,4.091
Vbulk1 on Bottom Layer "MidLayer4-PGND" (solid, pour order 314): 25.579,5.107 24.604,6.082 24.604,8.954 43.838,8.954 45.907,6.885 45.907,3.583 45.526,3.202 45.526,0.093 42.097,0.093 42.097,3.329 41.716,3.71 41.716,4.091 40.7,5.107
PGND on Bottom Layer "Bottom Layer-PGND" (solid, pour order 321): 41.248,25.072 42.102,25.927 42.102,31.507 42.238,31.643 42.505,31.643 42.705,31.443 42.705,25.417 43.05,25.072 46.809,25.072 49.137,22.744 50.891,22.744 52.058,23.911 52.058,32.727 50.612,34.174 47.658,34.174 45.372,31.888 43.308,31.888 43.054,32.142 42.705,32.491 42.705,34.174 35.625,34.174 34.863,34.936 33.451,34.936 32.946,34.431 32.946,25.702 33.575,25.072
SW on Bottom Layer "Bottom Layer-SW 2" (solid, pour order 317): 19.882,3.915 19.882,-0.083 24.073,-0.083 24.073,3.915
Neutral on Top Layer "TOP_LAYER_NEUTRAL_P354" (solid, pour order 354): 2.6,4.111 2.6,0 7,0 7,4.111
AGND on Top Layer "Top Layer-AGND" (solid, pour order 329): 55.591,2.567 55.336,2.822 55.336,3.33 55.717,3.711 56.489,3.711 56.842,4.092 56.842,5.616 57.232,6.006 58.756,6.006 59.146,5.616 59.145,3.167 58.595,2.567
PGND on Top Layer "Top Layer-PGND 2" (solid, pour order 325): 28.814,3.988 28.814,-0.01 32.878,-0.01 32.878,3.988
Vbulk1 on Top Layer "Top Layer-Vbulk+" (solid, pour order 324): 41.716,4.091 41.716,0.093 45.907,0.093 45.907,4.091
Vbulk1 on Top Layer "MidLayer4-PGND" (solid, pour order 322): 33.716,4.854 33.444,5.125 33.444,7.258 33.961,7.774 44.99,7.774 45.907,6.857 45.907,0.474 45.526,0.093 42.097,0.093 41.907,0.284 41.907,4.345 41.398,4.854
PGND on Top Layer "TOP_LAYER_PGND_P363" (solid, pour order 363): 8.52,35.349 8.52,30.839 8.177,30.496 0.962,30.496 0.489,30.969 0.489,35.258 0.94,35.709 8.177,35.709
NetQ1_1 on Top Layer "TOP_LAYER_NETQ1_1_P350" (solid, remove dead copper, pour order 350): 5.514,16.919 5.514,16.119 2.789,16.119 2.489,16.419 0.039,16.419 0.039,17.459 0.097,17.516 2.514,17.516 2.514,17.419 3.014,16.919
PGND on Top Layer "Top Layer-PGND" (solid, pour order 330): 41.131,12.464 42.992,10.603 45.024,10.603 45.278,10.349 45.278,9.206 45.02,8.949 34.081,8.908 33.573,9.416 33.573,11.702 34.335,12.464
SW on Top Layer "Top Layer-SW 1" (solid, pour order 326): 19.882,3.908 19.882,-0.09 24.073,-0.09 24.073,3.908
PGND on Top Layer "Top Layer-PGND 1" (solid, pour order 328): 48.161,28.072 45.271,28.072 45.271,29.774 48.681,29.774 49.812,28.643 49.812,26.421 49.558,26.167 48.542,26.167 48.288,26.421 48.288,27.945
PGND on Top Layer "Top Layer-PGND 1" (solid, pour order 327): 44.837,30.611 45.553,29.895 45.553,27.943 44.964,27.354 44.964,26.039 44.329,25.404 42.678,25.404 42.17,25.912 42.17,30.357 42.424,30.611
SW on Top Layer "Top Layer-SW" (solid, pour order 323): 44.964,17.589 41.716,17.589 41.716,16.725 42.392,16.049 42.392,14.236 42.788,13.839 45.201,13.839 47.36,13.839 48.122,13.077 48.122,11.002 49.347,11 50.09,11.743 50.09,12.249 49.265,13.349 49.265,14.892 48.839,15.318 48.073,14.552 46.948,14.552 45.705,15.795 45.705,18.33
Neutral on Top Layer "TOP_LAYER_NEUTRAL_P373" (solid, remove dead copper, pour order 373): 0.388,6.635 5.514,6.644 5.764,6.893 5.764,14.452 5.671,14.545 3.295,14.545 2.095,13.345 1.059,13.345 0.388,12.675
Neutral on Signal Layer 4 "SIGNAL_LAYER_4_NEUTRAL_P372" (solid, remove dead copper, pour order 372): 2.515,4.59 0.525,6.581 0.525,27.627 0.897,28 11.251,28 11.81,27.441 11.81,20.533 7,15.723 7,3.423 2.515,3.423
Neutral on Signal Layer 4 "SIGNAL_LAYER_4_NEUTRAL_P368" (solid, pour order 368): 2.6,4.111 2.6,0 7,0 7,4.111
PGND on Signal Layer 4 "SIGNAL_LAYER_4_PGND_P359" (solid, pour order 359): 0.342,36 38.493,36 41.081,33.412 41.081,30.426 31.582,20.927 29.191,20.927 24.162,25.956 19.761,25.956 14.625,31.091 0.362,31.091 0.362,36
AGND on Signal Layer 4 "MidLayer1-AGND" (solid, pour order 336): 61.75,5.811 59.496,3.557 59.496,2.567 59.496,0.093 52.384,0.093 52.384,6.494 55.555,9.665 55.555,35.746 61.238,35.746 61.75,35.234
PGND on Signal Layer 4 "MidLayer4-PGND 1" (solid, pour order 335): 29.524,30.888 28.814,30.178 28.814,9.881 29.533,9.162 36.446,9.162 38.75,11.466 38.75,29.917 37.779,30.888
PGND on Signal Layer 4 "MidLayer4-PGND 2" (solid, pour order 332): 28.814,0.093 28.814,15.521 35.244,15.521 35.244,10.344 32.752,7.852 32.752,0.093
SW on Signal Layer 4 "MidLayer1-SW" (solid, pour order 333): 51.114,13.046 49.78,11.711 44.292,11.711 42.605,13.398 42.605,16.878 44.171,18.444 50.921,18.444 51.114,18.25 51.114,14.632
Vbulk1 on Signal Layer 4 "MidLayer4-PGND" (solid, pour order 337): 34.744,7.774 34.335,7.365 34.335,5.516 34.744,5.107 41.145,5.107 42.082,4.17 42.082,0.093 45.553,0.093 45.553,7.239 45.018,7.774
PGND on Signal Layer 4 "MidLayer1-PGND" (solid, pour order 334): 42.649,24.041 43.362,23.327 50.27,23.327 51.114,24.172 51.114,29.872 48.955,32.031 44.015,32.031 42.649,30.664
Neutral on Top Solder (solid): 2.617,4.116 6.808,4.116 6.808,0.179 6.747,0.118 2.617,0.118
no net on Top Solder (solid): 28.814,3.988 32.878,3.988 32.878,-0.01 28.814,-0.01
no net on Top Solder (solid): 41.716,4.091 45.907,4.091 45.907,0.093 41.716,0.093
no net on Top Solder (solid): 19.838,3.932 24.029,3.932 24.029,-0.005 23.968,-0.065 19.838,-0.065
Neutral on Signal Layer 2 "SIGNAL_LAYER_2_NEUTRAL_P371" (solid, remove dead copper, pour order 371): 2.515,4.314 0.525,6.304 0.525,27.856 1.207,28.538 12.069,28.538 12.5,28.107 12.5,21.515 7,16.015 7,3.423 2.515,3.423
Neutral on Signal Layer 2 "SIGNAL_LAYER_2_NEUTRAL_P366" (solid, pour order 366): 2.6,4.111 2.6,0 7,0 7,4.111
PGND on Signal Layer 2 "SIGNAL_LAYER_2_PGND_P361" (solid, pour order 361): 0.933,31.5 0.933,35.523 10.403,35.523 10.403,31.5
Vbulk1 on Signal Layer 2 "MidLayer4-PGND" (solid, pour order 342): 35.186,5.107 34.335,5.957 34.335,7.507 35.11,8.282 44.51,8.282 45.908,6.884 45.908,0.093 41.907,0.093 41.907,4.345 41.145,5.107
AGND on Signal Layer 2 "MidLayer2-AGND" (solid, pour order 340): 20.597,21.119 20.266,21.45 20.266,33.2 23.067,36 48.193,36 48.193,33.174 33.588,33.174 25.397,24.983 25.397,21.969 24.548,21.119
AGND on Signal Layer 2 "MidLayer1-AGND" (solid, pour order 339): 62,6.104 59.496,3.6 59.496,0.093 52.384,0.093 52.384,7.012 55.527,10.154 55.527,31.217 53.569,33.174 47.851,33.174 47.851,35.638 61.346,35.638 62,34.984
SW on Signal Layer 2 "MidLayer3-SW 1" (solid, pour order 338): 23.956,4.429 23.956,0 20.25,0 20.25,11.752 30.397,21.899 41.185,21.899 41.716,21.367 41.716,20.41 41.335,20.029 39.557,20.029 25.333,5.805
SW on Signal Layer 2 "MidLayer1-SW" (solid, pour order 341): 42.5,11.57 42.13,11.941 42.13,17.07 43.168,18.108 45.514,18.108 48.527,21.121 49.921,21.121 51.114,19.928 51.114,19.204 51.114,14.632 51.114,13.171 49.513,11.57
PGND on Signal Layer 1 "MidLayer1-PGND" (solid, pour order 357): 43.229,30.634 42.4,29.805 42.4,25.095 43.917,23.578 50.52,23.578 51.114,24.172 51.114,29.872 50.352,30.634
Neutral on Signal Layer 1 "SIGNAL_LAYER_1_NEUTRAL_P369" (solid, pour order 369): 2.6,4.111 2.6,0 7,0 7,4.111
PGND on Signal Layer 1 "SIGNAL_LAYER_1_PGND_P362" (solid, pour order 362): 0.489,31.091 0.489,35.523 9.522,35.523 9.522,31.091
AGND on Signal Layer 1 "MidLayer1-AGND" (solid, pour order 358): 61.75,5.811 59.496,3.557 59.496,0.093 52.384,0.093 52.384,7.012 52.765,7.393 55.527,10.154 55.527,31.033 53.11,33.45 32.928,33.45 24.889,25.411 24.889,21.461 24.548,21.119 20.597,21.119 20.25,21.466 20.25,33.183 22.705,35.638 61.346,35.638 61.75,35.234
Vbulk1 on Signal Layer 1 "MidLayer4-PGND" (solid, pour order 343): 41.716,4.091 40.7,5.107 40.51,5.107 34.536,5.107 34.536,8.282 44.51,8.282 45.908,6.884 45.908,0.093 41.716,0.093
SW on Signal Layer 1 "MidLayer1-SW" (solid, pour order 344): 48.047,21.121 50.404,21.121 51.114,20.411 51.114,13.171 49.513,11.57 42.5,11.57 42.13,11.941 42.13,17.427 42.892,18.189 45.114,18.189
PGND on Signal Layer 1 "MidLayer1-PGND" (solid, pour order 356): 27.75,5.607 29.173,4.183 29.173,-0.01 32.572,-0.01 32.572,20.28 39.497,27.205 41.081,28.789 41.081,31.935 40.561,32.455 36.217,32.455 27.75,23.989
Neutral on Bottom Solder (solid): 2.587,4.115 6.778,4.115 6.778,0.118 2.587,0.118
no net on Bottom Solder (solid): 28.814,3.988 32.878,3.988 32.878,-0.01 28.814,-0.01
no net on Bottom Solder (solid): 41.716,4.091 45.907,4.091 45.907,0.093 41.716,0.093
no net on Bottom Solder (solid): 19.838,3.932 24.029,3.932 24.029,-0.065 19.838,-0.065
Neutral on Signal Layer 3 "SIGNAL_LAYER_3_NEUTRAL_P367" (solid, pour order 367): 2.6,4.111 2.6,0 7,0 7,4.111
Vbulk1 on Signal Layer 3 "SIGNAL_LAYER_3_VBULK1_P364" (solid, remove dead copper, pour order 364): 31.683,10.01 33.26,8.433 33.26,7.117 31.25,5.107 25.638,5.107 24.939,5.806 9.936,5.806 8.107,7.635 8.107,17.122 8.52,17.535 16.009,17.535 17.07,16.474 17.07,14.173 21.233,10.01
PGND on Signal Layer 3 "SIGNAL_LAYER_3_PGND_P360" (solid, pour order 360): 0.362,31.091 0.362,35.638 10.403,35.638 10.403,31.091
Vbulk1 on Signal Layer 3 "MidLayer4-PGND" (solid, pour order 345): 41.716,4.091 40.7,5.107 30.794,5.107 30.667,5.233 30.667,9.171 30.807,9.311 43.481,9.311 45.908,6.884 45.908,0.093 41.716,0.093

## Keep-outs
Keep-Out Layer:
  text ".Layer_Name" at 14.656,-21.806 h1.52

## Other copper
Top Layer:
  text ".Layer_Name" at 14.656,-21.806 h1.52
Bottom Layer:
  pour cut-out: 21.222,31.581 ccw(c24.463,32.732) 27.705,33.882 ccw(c24.463,32.732)
  text ".Layer_Name" at 14.656,-21.806 h1.52

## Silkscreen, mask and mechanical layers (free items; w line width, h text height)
Top Overlay:
  lines w0.254: 61.158,12.551 61.158,13.516
  text ".Layer_Name" at 14.656,-21.806 h1.52
Bottom Overlay:
  lines w0.254: 0.5,33.968 0.5,36 2.532,36 ; 15.968,7 18,7 18,9.032 ; 57.152,35.991 59.25,36 59.259,33.968 ; 57.228,7 59.26,7 59.259,9.032
  text ".Layer_Name" at 14.656,-21.806 h1.52
Top Paste:
  text ".Layer_Name" at 14.656,-21.806 h1.52
Bottom Paste:
  text ".Layer_Name" at 14.656,-21.806 h1.52
Top Solder:
  rectangle: 12.559,0.18 13.359,3.437
  rectangle: 11.395,0.18 12.195,3.437
  rectangle: 8.686,0.18 9.486,3.437
  rectangle: 7.645,0.18 8.445,3.437
  rectangle: 52.987,0.09 53.787,3.348
  rectangle: 54.257,0.09 55.057,3.348
  rectangle: 55.527,0.09 56.327,3.348
  rectangle: 56.797,0.09 57.597,3.348
  rectangle: 58.067,0.09 58.867,3.348
  region: 7.621,33.33 7.621,30.83 8.421,30.83 8.421,33.33
  region: 6.421,33.33 6.421,30.83 7.221,30.83 7.221,33.33
  region: 5.221,33.33 5.221,30.83 6.021,30.83 6.021,33.33
  region: 4.021,33.33 4.021,30.83 4.821,30.83 4.821,33.33
  region: 2.821,33.33 2.821,30.83 3.621,30.83 3.621,33.33
  rectangle: 1.621,30.83 8.021,31.33
  region: 1.621,33.33 1.621,30.83 2.421,30.83 2.421,33.33
  region: 5.678,8.145 5.678,14.545 5.178,14.545 5.178,8.145
  rectangle: 3.17,13.745 5.67,14.545
  rectangle: 3.17,12.545 5.67,13.345
  rectangle: 3.17,11.345 5.67,12.145
  rectangle: 3.17,10.145 5.67,10.945
  rectangle: 3.17,7.741 5.67,8.541
  rectangle: 3.17,8.935 5.67,9.735
  text ".Layer_Name" at 14.656,-21.806 h1.52
  text ".Layer_Name" at 14.656,-21.806 h1.52
Bottom Solder:
  rectangle: 12.559,0.18 13.359,3.437
  rectangle: 11.395,0.18 12.195,3.437
  rectangle: 8.686,0.18 9.486,3.437
  rectangle: 7.645,0.18 8.445,3.437
  rectangle: 52.987,0.09 53.787,3.348
  rectangle: 55.527,0.09 56.327,3.348
  rectangle: 58.067,0.09 58.867,3.348
  rectangle: 56.797,0.09 57.597,3.348
  rectangle: 54.257,0.09 55.057,3.348
  rectangle: 8.038,7.244 17.07,17.535
  rectangle: 0.525,19.976 11.75,28.538
  text ".Layer_Name" at 14.656,-21.806 h1.52
Drill Guide:
  text ".Layer_Name" at 14.656,-21.806 h1.52
M1 Board Outline:
  lines w0.254: 2.515,0.085 2.515,3.956 2.471,4 0,4 0,36 62,36 62,4 59.499,4 59.496,3.997 59.496,0 52.096,0 52.006,0.09 52.003,0.093 52.003,3.997 45.907,3.997 45.907,0 41.809,0 41.716,0.093 41.716,3.932 41.649,4 33.271,4 32.973,4 ; 2.6,0 13.787,0 13.787,4 17.792,4 19.908,4 19.908,0 24.143,0 24.143,4.091 ; 24.283,3.988 28.814,3.988 ; 28.829,3.969 28.829,0 32.953,0 32.953,3.981
  text ".Layer_Name" at 14.656,-21.806 h1.52
M2 Board Dimensions:
  rectangle: 0,-6.985 3.175,-3.81
  rectangle: 3.175,-10.16 12.7,-6.985
  lines w0.178: 0,-6.985 25.4,-6.985 ; 3.175,-10.16 3.175,-3.81 ; 6.35,-10.16 6.35,-3.81 ; 12.7,-10.16 12.7,-3.81 ; 19.05,-10.16 19.05,-3.81 ; 0,-10.16 25.4,-10.16 25.4,-3.81 0,-3.81 0,-10.16
  text ".Layer_Name" at 14.656,-21.806 h1.52
M3 3D STEP Top:
  text ".Layer_Name" at 14.656,-21.806 h1.52
M4 3D STEP Bottom:
  text ".Layer_Name" at 14.656,-21.806 h1.52
M5 Assembly Top:
  lines w0.254: -7.417,-23.626 160.223,-23.626 ; -7.417,-18.462 160.274,-18.462 ; -7.417,-13.297 -7.417,-28.791 94.31,-28.791 160.274,-28.791 160.274,-13.297 -7.404,-13.297 -7.404,-28.791 32.614,-28.791 ; 55.194,-28.791 55.194,-13.297 ; 87.376,-18.462 87.376,-13.297 ; 108.712,-18.462 108.712,-13.297 ; 124.511,-28.956 124.511,-23.804
  text "COMPONENTS MARKED 'DNP' SHOULD NOT BE POPULATED." at 29.299,-8.09 h1.52
  text "ASSEMBLY VARIANT:" at 29.286,-11.024 h1.52
  text ".VariantName" at 55.601,-11.024 h1.52
  text "PCB VIEWED FROM TOP SIDE" at -5.804,-16.654 h1.52
  text "BOARD #:" at 57.099,-16.654 h1.52
  text ".PRJ_Number" at 70.955,-16.654 h1.52
  text "REV:" at 92.405,-16.654 h1.52
  text ".PCB_Rev" at 99.809,-16.654 h1.52
  text "SVN REV:" at 113.69,-16.654 h1.52
  text ".VersionControl_RevNumber" at 126.543,-16.654 h1.52
  text "TID #:" at 57.099,-21.819 h1.52
  text ".TID" at 70.955,-21.819 h1.52
  text "PLOT NAME =" at -5.804,-27.034 h1.52
  text ".plot_File_Name" at 14.656,-27.034 h1.52
  text "GENERATED    :" at 57.15,-27.034 h1.52
  text ".Print_Date" at 79.235,-27.034 h1.52
  text ".Print_Time" at 97.752,-27.034 h1.52
  text "TEXAS INSTRUMENTS" at 129.87,-27.034 h1.52
M6 Assembly Bottom:
  lines w0.254: -7.429,-18.474 160.261,-18.474 ; -7.379,-23.639 160.261,-23.639 ; 28.334,-28.969 28.334,-23.817 ; 44.133,-18.474 44.133,-13.31 ; 65.468,-18.474 65.468,-13.31 ; 97.65,-28.804 97.65,-13.31 ; 120.231,-28.804 160.249,-28.804 160.249,-13.31 -7.429,-13.31 -7.429,-28.804 58.534,-28.804 160.261,-28.804 160.261,-13.31
  text "COMPONENTS MARKED 'DNP' SHOULD NOT BE POPULATED." at 154.991,-8.077 h1.52
  text ".VariantName" at 128.473,-11.024 h1.52
  text "ASSEMBLY VARIANT:" at 154.864,-11.024 h1.52
  text ".VersionControl_RevNumber" at 26.302,-16.667 h1.52
  text "SVN REV:" at 39.154,-16.667 h1.52
  text ".PCB_Rev" at 53.035,-16.667 h1.52
  text "REV:" at 60.439,-16.667 h1.52
  text ".PRJ_Number" at 81.89,-16.667 h1.52
  text "BOARD #:" at 95.745,-16.667 h1.52
  text "PCB VIEWED FROM BOTTOM SIDE" at 158.648,-16.667 h1.52
  text ".TID" at 81.89,-21.831 h1.52
  text "TID #:" at 95.745,-21.831 h1.52
  text "TEXAS INSTRUMENTS" at 22.974,-27.047 h1.52
  text ".Print_Time" at 55.093,-27.047 h1.52
  text ".Print_Date" at 73.609,-27.047 h1.52
  text "GENERATED    :" at 95.694,-27.047 h1.52
  text ".plot_File_Name" at 138.189,-27.047 h1.52
  text "PLOT NAME =" at 158.648,-27.047 h1.52
M9 Title Sheet:
  drawing of 57 lines, arcs and shapes, not listed
  text "1" at 18.792,204.127 h1.78
  text "2" at 82.182,204.127 h1.78
  text "3" at 145.411,204.127 h1.78
  text "4" at 209.08,204.127 h1.78
  text "5" at 272.555,204.127 h1.78
  text "6" at 336.182,204.127 h1.78
  text "A" at -10.579,175.095 h1.78
  text "A" at 365.341,175.095 h1.78
  text "B" at -10.579,114.643 h1.78
  text "B" at 365.341,114.643 h1.78
  text "C" at -10.579,54.318 h1.78
  text "C" at 365.341,54.318 h1.78
  text "PROJECT TITLE:" at 288.125,7.048 h1.14
  text ".PRJ_Title" at 289.395,3.662 h1.78
  text "DESIGNED FOR:" at 288.125,-0.597 h1.14
  text ".PRJ_Customer" at 289.395,-4.153 h1.78
  text "D" at -10.579,-5.88 h1.78
  text "D" at 365.341,-5.88 h1.78
  text "FILE NAME:" at 288.125,-8.217 h1.14
  text ".PCB_File_Name_No_Path" at 289.395,-11.265 h1.78
  text "Texas Instruments (TI) and/or its licensors do not warrant the accuracy or completeness of this specification" at 161.9,-15.376 h1.14
  text "ENGINEER:" at 288.125,-15.583 h1.14
  text "LAYOUT BY:" at 326.352,-15.583 h1.14
  text "or any information contained therein. TI and/or its licensors do not warrant that this design will meet" at 160.757,-18.237 h1.14
  text ".PRJ_Engineer" at 289.395,-19.52 h1.78
  text ".PCB_Layout" at 327.635,-19.52 h1.78
  text "the specifications, will be suitable for your application or fit for any particular purpose, or will operate in" at 160.757,-21.099 h1.14
  text ".Layer_Name" at 14.656,-21.806 h1.52
  text "ALTIUM DESIGNER VERSION:" at 326.352,-23.457 h1.14
  text "an implementation. TI and/or its licensors do not warrant that the design is production worthy. You should" at 160.757,-23.961 h1.14
  text "completely validate and test your design implementation to confirm the system functionality for your application." at 161.9,-26.822 h1.14
  text ".print_Scale" at 289.395,-26.843 h1.78
  text ".Application_BuildNumber" at 327.635,-26.843 h1.78
  text "1" at 18.792,-32.093 h1.78
  text "2" at 82.182,-32.093 h1.78
  text "3" at 145.411,-32.093 h1.78
  text "4" at 209.08,-32.093 h1.78
  text "5" at 272.555,-32.093 h1.78
  text "6" at 336.182,-32.093 h1.78
M10 Fab Notes:
  drawing of 189 lines, arcs and shapes, not listed
  text "DESIGN INFORMATION" at 314.503,161.447 h1.52
  text "MIN. TRACK WIDTH:" at 298.131,158.091 h1.52
  text "8" at 325.976,158.091 h1.52
  text "MIL" at 329.907,158.091 h1.52
  text "7.874" at 321.75,155 h1.52
  text "MIN. CLEARANCE:" at 298.131,154.938 h1.52
  text "MIL" at 329.907,154.938 h1.52
  text "MIN. VIA PAD SIZE:" at 298.131,151.785 h1.52
  text "24" at 325.214,151.785 h1.52
  text "MIL" at 329.907,151.785 h1.52
  text "0.05mm (2MIL)" at 315.784,148.486 h1.52
  text "MINIMUM ANNULAR RING" at 289.769,148.277 h1.52
  text "EXTERNAL" at 333.768,148.277 h1.52
  text "PER" at 294.849,145.48 h1.52
  text "IPC-D-275 CLASS 2 LEVEL C" at 300.437,145.48 h1.52
  text "MIL, HOLES" at 338.238,142.928 h1.52
  text "+/-" at 328.27,142.709 h1.52
  text "+/-" at 349.961,142.709 h1.52
  text "REGISTRATION TOLERANCES:" at 289.769,142.682 h1.52
  text "METAL" at 320.243,142.682 h1.52
  text "5" at 334.879,142.683 h1.52
  text "3" at 356.037,142.683 h1.52
  text "MIL" at 358.99,142.682 h1.52
  text "HOLE SIZE TOLERANCE (UNLESS OTHERWISE SPECIFIED):" at 289.769,140.185 h1.52
  text "+/-" at 349.961,140.112 h1.52
  text "3" at 356.037,140.085 h1.52
  text "MIL" at 358.99,140.085 h1.52
  text "MATERIAL:" at 287.87,136.589 h1.52
  text "FR-4 High Tg" at 312.926,133.324 h1.52
  text "X" at 309.257,133.122 h1.52
  text "FR-408" at 298.563,133.007 h1.52
  text "OTHER" at 336.358,133.007 h1.52
  text "62 MIL (1.6mm) +/-10%" at 306.694,129.374 h1.52
  text "X" at 303.643,129.312 h1.52
  text "THICKNESS:" at 289.769,129.165 h1.52
  text "OTHER" at 339.33,129.165 h1.52
  text "TOLERANCE:" at 289.769,125.652 h1.52
  text "X" at 311.314,125.652 h1.52
  text "ANSI IPC-6012 TYPE 3 CLASS 2" at 315.836,125.652 h1.52
  text "OTHER +/-" at 315.835,121.989 h1.52
  text "BOW & TWIST:" at 289.769,118.302 h1.52
  text "X" at 311.314,118.302 h1.52
  text "ANSI IPC-6012 TYPE 3 CLASS 2" at 315.836,118.302 h1.52
  text "OTHER +/-" at 315.835,114.576 h1.52
  text "DRILLING:" at 287.87,111.258 h1.52
  text "NC_DRILL FILES" at 332.599,108.586 h1.52
  text "REFERENCE:" at 289.769,108.486 h1.52
  text "X" at 306.463,108.484 h1.52
  text "AS SHOWN" at 310.984,108.486 h1.52
  text "X" at 329.348,108.486 h1.52
  text "OTHER" at 340.168,104.873 h1.52
  text "PTH COPPER THICKNESS:" at 289.761,104.783 h1.52
  text "X" at 318.697,104.783 h1.52
  text "20-30 um" at 321.948,104.783 h1.52
  text "BOARD FINISH:" at 287.87,101.034 h1.52
  text "SILKSCREEN:" at 291.812,98.237 h1.52
  text "X" at 316.14,98.237 h1.52
  text "TOP" at 319.112,98.237 h1.52
  text "X" at 329.094,98.237 h1.52
  text "BOTTOM" at 332.091,98.237 h1.52
  text "SILKSCREEN COLOR:" at 291.812,94.295 h1.52
  text "X" at 316.115,94.295 h1.52
  text "WHITE" at 319.112,94.295 h1.52
  text "OTHER" at 332.091,94.295 h1.52
  text "X" at 319.442,90.652 h1.52
  text "GREEN" at 322.439,90.652 h1.52
  text "OTHER" at 338.136,90.652 h1.52
  text "SOLDER RESIST COLOR:" at 291.812,90.477 h1.52
  text "X" at 319.442,86.734 h1.52
  text "MATTE" at 322.439,86.734 h1.52
  text "SEMI-GLOSS" at 338.125,86.717 h1.52
  text "IMMERSION GOLD (ENIG)" at 314.819,82.345 h1.52
  text "ENEPIG" at 348.793,82.162 h1.52
  text "SURFACE FINISH:" at 287.87,82.136 h1.52
  text "X" at 310.298,82.136 h1.52
  text "IMM. TIN/SILVER OR EQUIV" at 296.24,78.649 h1.52
  text "OTHER" at 332.599,78.549 h1.52
  text "ARRAY/PANEL:" at 287.87,74.602 h1.52
  text "CUT AND TRIM PER M1 BOARD OUTLINE" at 314.819,74.393 h1.52
  text "N.C. ROUTE" at 314.819,70.94 h1.52
  text "X" at 332.295,70.94 h1.52
  text "V. SCORE" at 336.816,70.94 h1.52
  text "CERTIFICATION:" at 287.87,67.66 h1.52
  text "MATERIALS AND WORKMANSHIP FOR ALL PCBS" at 306.285,67.66 h1.52
  text "TO MEET OR EXCEED THE REQUIREMENTS OF:" at 306.285,65.271 h1.52
  text "X" at 297.078,62.003 h1.52
  text "ANSI IPC-A-600F CLASS ->" at 300.329,62.003 h1.52
  text "X" at 342.188,62.003 h1.52
  text "2" at 344.982,62.003 h1.52
  text "1" at 336.981,61.965 h1.52
  text "3" at 353.973,61.965 h1.52
  text "X" at 317.702,58.252 h1.52
  text "RoHS" at 320.953,58.252 h1.52
  text "OTHER" at 337.321,58.252 h1.52
  text "PER ORDER" at 347.407,58.252 h1.52
  text "ALL BOARDS MUST MEET OR EXCEED UL94-V0 REQUIREMENTS." at 288.569,54.345 h1.52
  text "PCB MUST BEAR THE UL94V-0 UL REGISTERED MATERIAL ID NUMBER" at 288.569,51.397 h1.52
  text "ADDITIONAL REQUIREMENTS:" at 287.87,47.094 h1.52
  text "MICROSECTION:" at 289.769,44.373 h1.52
  text "YES" at 312.775,44.373 h1.52
  text "REQUIRED" at 334.657,40.707 h1.52
  text "BARE BOARD ELEC. TEST:" at 289.769,40.634 h1.52
  text "NONE" at 322.935,40.634 h1.52
  text "X" at 331.66,40.634 h1.52
  text "PER ORDER" at 349.693,40.634 h1.52
  text "XX MIL VIAS REQUIRE NON-CONDUCTIVE FILL AND PLANARIZE" at 294.04,35.428 h1.5
  text "XX MIL VIAS REQUIRE CONDUCTIVE FILL AND PLANARIZE" at 294.243,32.787 h1.52
  text "OUTER XX MIL TRACES REQUIRE 50 OHM SINGLE-ENDED IMPEDANCE" at 294.218,28.637 h1.47
  text "LAYER 2 & 3 (INNER LAYERS) XX MIL WIDE, XX MIL SPACE / TRACES REQUIRE 100 OHM DIFFERENTIAL IMPEDANCE" at 294.015,22.65 h1.52
  text ".Layer_Name" at 14.656,-21.806 h1.52
M11 Gerber Information:
  lines w0.254: -7.417,-23.626 160.223,-23.626 ; -7.417,-18.462 160.274,-18.462 ; -7.417,-13.297 -7.417,-28.791 94.31,-28.791 160.274,-28.791 160.274,-13.297 -7.404,-13.297 -7.404,-28.791 32.614,-28.791 ; 55.194,-28.791 55.194,-13.297 ; 87.376,-18.462 87.376,-13.297 ; 108.712,-18.462 108.712,-13.297 ; 124.511,-28.956 124.511,-23.804
  text "ALL ARTWORK VIEWED FROM TOP SIDE" at -5.804,-16.654 h1.52
  text "BOARD #:" at 57.099,-16.654 h1.52
  text ".PRJ_Number" at 70.955,-16.654 h1.52
  text "REV:" at 92.405,-16.654 h1.52
  text ".PCB_Rev" at 99.809,-16.654 h1.52
  text "SVN REV:" at 113.69,-16.654 h1.52
  text ".VersionControl_RevNumber" at 126.543,-16.654 h1.52
  text "LAYER NAME =" at -5.804,-21.806 h1.52
  text "TID #:" at 57.099,-21.819 h1.52
  text ".TID" at 70.955,-21.819 h1.52
  text "PLOT NAME =" at -5.804,-27.034 h1.52
  text ".plot_File_Name" at 14.656,-27.034 h1.52
  text "GENERATED    :" at 57.15,-27.034 h1.52
  text ".Print_Date" at 79.235,-27.034 h1.52
  text ".Print_Time" at 97.752,-27.034 h1.52
  text "TEXAS INSTRUMENTS" at 129.87,-27.034 h1.52
M12 Stackup:
  drawing of 399 lines, arcs and shapes, not listed
  text "Layer" at 249.215,193.165 h1.52
  text "Name" at 259.626,193.165 h1.52
  text "Material" at 283.496,193.165 h1.52
  text "Thickness" at 305.334,193.165 h1.52
  text "Constant" at 321.84,193.165 h1.52
  text "Board Layer Stack" at 336.314,193.165 h1.52
  text "1" at 249.215,190.117 h1.52
  text "Top Overlay" at 259.626,190.117 h1.52
  text "2" at 249.215,187.069 h1.52
  text "Top Solder" at 259.626,187.069 h1.52
  text "Solder Resist" at 283.496,187.069 h1.52
  text "0.50mil" at 305.334,187.069 h1.52
  text "3.5" at 321.84,187.069 h1.52
  text "3" at 249.215,184.021 h1.52
  text "Top Layer" at 259.626,184.021 h1.52
  text "Copper" at 283.496,184.021 h1.52
  text "2.80mil" at 305.334,184.021 h1.52
  text "4" at 249.215,180.973 h1.52
  text "Dielectric 1" at 259.626,180.973 h1.52
  text "FR-4 High Tg" at 283.496,180.973 h1.52
  text "7.00mil" at 305.334,180.973 h1.52
  text "4.2" at 321.84,180.973 h1.52
  text "5" at 249.215,177.925 h1.52
  text "Signal Layer 1" at 259.626,177.925 h1.52
  text "Copper" at 283.496,177.925 h1.52
  text "2.80mil" at 305.334,177.925 h1.52
  text "6" at 249.215,174.877 h1.52
  text "Dielectric 2" at 259.626,174.877 h1.52
  text "FR-4 High Tg" at 283.496,174.877 h1.52
  text "14.00mil" at 305.334,174.877 h1.52
  text "4.2" at 321.84,174.877 h1.52
  text "7" at 249.215,171.829 h1.52
  text "Signal Layer 2" at 259.626,171.829 h1.52
  text "Copper" at 283.496,171.829 h1.52
  text "2.80mil" at 305.334,171.829 h1.52
  text "8" at 249.215,168.781 h1.52
  text "Dielectric 4" at 259.626,168.781 h1.52
  text "FR-4 High Tg" at 283.496,168.781 h1.52
  text "11.00mil" at 305.334,168.781 h1.52
  text "4.2" at 321.84,168.781 h1.52
  text "9" at 249.215,165.733 h1.52
  text "Signal Layer 3" at 259.626,165.733 h1.52
  text "Copper" at 283.496,165.733 h1.52
  text "2.80mil" at 305.334,165.733 h1.52
  text "10" at 249.215,162.685 h1.52
  text "Dielectric 5" at 259.626,162.685 h1.52
  text "FR-4 High Tg" at 283.496,162.685 h1.52
  text "14.00mil" at 305.334,162.685 h1.52
  text "4.2" at 321.84,162.685 h1.52
  text "11" at 249.215,159.637 h1.52
  text "Signal Layer 4" at 259.626,159.637 h1.52
  text "Copper" at 283.496,159.637 h1.52
  text "2.80mil" at 305.334,159.637 h1.52
  text "12" at 249.215,156.589 h1.52
  text "Dielectric 3" at 259.626,156.589 h1.52
  text "FR-4 High Tg" at 283.496,156.589 h1.52
  text "7.00mil" at 305.334,156.589 h1.52
  text "4.2" at 321.84,156.589 h1.52
  text "13" at 249.215,153.541 h1.52
  text "Bottom Layer" at 259.626,153.541 h1.52
  text "Copper" at 283.496,153.541 h1.52
  text "2.80mil" at 305.334,153.541 h1.52
  text "14" at 249.215,150.493 h1.52
  text "Bottom Solder" at 259.626,150.493 h1.52
  text "Solder Resist" at 283.496,150.493 h1.52
  text "0.50mil" at 305.334,150.493 h1.52
  text "3.5" at 321.84,150.493 h1.52
  text "15" at 249.215,147.445 h1.52
  text "Bottom Overlay" at 259.626,147.445 h1.52
  text ".Layer_Name" at 14.656,-21.806 h1.52
M13 Component Bodies Top:
  text ".Layer_Name" at 14.656,-21.806 h1.52
M14 Component Bodies Bottom:
  text ".Layer_Name" at 14.656,-21.806 h1.52
M15 Courtyards Top:
  text ".Layer_Name" at 14.656,-21.806 h1.52
M16 Courtyards Bottom:
  text ".Layer_Name" at 14.656,-21.806 h1.52
Drill Drawing:
  circle w0.254: c136.238,72.771 r0.702
  lines w0.254: 135.537,75.227 136.94,75.227 136.94,76.631 135.537,76.631 135.537,75.227 ; 135.537,78.736 135.888,78.736 136.238,78.385 136.589,78.736 136.94,78.736 136.589,79.087 136.94,79.437 136.589,79.437 136.238,79.788 135.888,79.437 135.537,79.437 135.888,79.087 135.537,78.736 ; 135.537,82.946 136.94,82.946 136.238,81.543 135.537,82.946 ; 135.537,84.7 136.238,85.051 136.94,84.7 136.589,85.402 136.94,86.104 136.238,85.753 135.537,86.104 135.888,85.402 135.537,84.7
  lines w0.305: 134.264,71.122 216.344,71.122 ; 134.264,86.911 216.344,86.911 ; 142.846,67.964 142.846,90.068 ; 151.279,67.964 151.279,90.068 ; 167.448,67.964 167.448,90.068 ; 174.03,67.964 174.03,90.068 ; 183.559,67.964 183.559,90.068 ; 201.957,67.964 201.957,90.068 ; 134.264,67.964 216.344,67.964 216.344,90.068 134.264,90.068 134.264,67.964
  text "Symbol" at 136.159,87.858 h1.83
  text "Quantity" at 143.793,87.858 h1.83
  text "Finished Hole Size" at 152.226,87.858 h1.83
  text "Plated" at 168.395,87.858 h1.83
  text "Hole Type" at 174.977,87.858 h1.83
  text "Drill Layer Pair" at 184.506,87.858 h1.83
  text "Hole Tolerance" at 202.904,87.858 h1.83
  text "568" at 143.793,84.7 h1.52
  text "7.87mil (0.200mm)" at 152.226,84.7 h1.52
  text "PTH" at 168.395,84.7 h1.52
  text "Round" at 174.977,84.7 h1.52
  text "Top Layer - Bottom Layer" at 184.506,84.7 h1.52
  text "175" at 143.793,81.543 h1.52
  text "10.00mil (0.254mm)" at 152.226,81.543 h1.52
  text "PTH" at 168.395,81.543 h1.52
  text "Round" at 174.977,81.543 h1.52
  text "Top Layer - Bottom Layer" at 184.506,81.543 h1.52
  text "32" at 143.793,78.385 h1.52
  text "12.00mil (0.305mm)" at 152.226,78.385 h1.52
  text "PTH" at 168.395,78.385 h1.52
  text "Round" at 174.977,78.385 h1.52
  text "Top Layer - Bottom Layer" at 184.506,78.385 h1.52
  text "2" at 143.793,75.227 h1.52
  text "39.37mil (1.000mm)" at 152.226,75.227 h1.52
  text "PTH" at 168.395,75.227 h1.52
  text "Round" at 174.977,75.227 h1.52
  text "Top Layer - Bottom Layer" at 184.506,75.227 h1.52
  text "2" at 143.793,72.069 h1.52
  text "125.98mil (3.200mm)" at 152.226,72.069 h1.52
  text "PTH" at 168.395,72.069 h1.52
  text "Round" at 174.977,72.069 h1.52
  text "Top Layer - Bottom Layer" at 184.506,72.069 h1.52
  text "779 Total" at 143.793,68.912 h1.52
  text ".Layer_Name" at 14.656,-21.806 h1.52
M17 Embedded Cavity:
  text ".Layer_Name" at 14.656,-21.806 h1.52
M18 Embedded Assembly:
  text ".Layer_Name" at 14.656,-21.806 h1.52
M19 Embedded Keepout:
  text ".Layer_Name" at 14.656,-21.806 h1.52

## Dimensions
0,-10.16 to 25.4,-10.16 on M2 Board Dimensions
0,0 to 0,36 on M2 Board Dimensions
0,0 to 62,4 on M2 Board Dimensions
62,4 to 54.126,7.901 on M2 Board Dimensions
62,4 to 63.75,10.949 on M2 Board Dimensions
62,36 to 24.395,34.555 on M2 Board Dimensions
0,36 to 19.25,32.692 on M2 Board Dimensions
